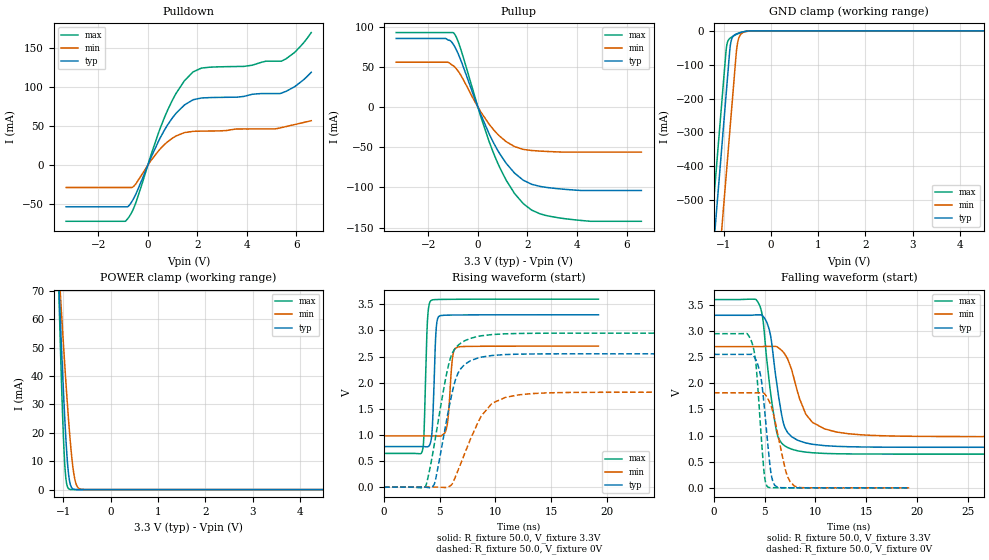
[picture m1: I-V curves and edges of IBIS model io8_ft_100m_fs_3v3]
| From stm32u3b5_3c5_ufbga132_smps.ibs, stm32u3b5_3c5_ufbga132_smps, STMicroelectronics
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[Model]   io8_ft_100m_fs_3v3
Model_type I/O
Polarity   Non-Inverting
Enable   Active-Low
| CAP_THRESHOLD on pad IOFT is "UDTCAPC" :
| Rising=30.0% of vddiom   Falling=70.0% of vddiom
| C_comp min and max val. don't necessarily correlate with the min and max pvt
| but are the smallest and greatest pad capacitance found.
| var   typ   min   max
C_comp   3.79549pF  3.74406pF  3.79817pF
|C_comp_pullup   2.32785pF  2.17309pF  2.40205pF
|C_comp_pulldown   1.46764pF  1.57097pF  1.39612pF
Vinl = 1.35V
Vinh = 1.8V
Vmeas = 1.65V   | Reference voltage for timing measurements
Cref  = 50.0pF   | Timing specification test load capacitance value
Rref  = 1.0MOhm   | Timing specification test load resistance value
Vref  = 1.815V   | Timing specification test load voltage
[Model Spec]
| TIME_THRESHOLD on pin ZIV11 is "CMOS" :
| Rising=50.0% of vdd   Falling=50.0% of vdd
Vinl 1.27950V 1.06950V 1.36550V
Vinh 1.78950V 1.51350V 1.89450V
| variable   typ   min   max
[Temperature Range] 25.0 130.0 -40.0
| variable   typ   min   max
[Voltage Range] 3.3V 2.7V 3.6V
| variable   typ   min   max
[POWER Clamp Reference] 3.3V 2.7V 3.6V
| variable   typ   min   max
[GND Clamp Reference] 0V 0V 0V
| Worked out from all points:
|   slope of the pulldown table from 0 to 0.495 V, typ, clamps not added: 14.3 ohm
|   slope of the pullup table from 0 to 0.495 V, typ, clamps not added: 13.8 ohm
|   GND clamp passes 1 mA (typ) near -0.50 V on its own axis
|   POWER clamp passes 1 mA (typ) near -0.83 V on its own axis
|   rising waveform, R_fixture 50.0, V_fixture 3.3V: 20-80 % time 252ps typ, 335ps min, 240ps max; typ from 0.776 V to 3.3 V
|   falling waveform, R_fixture 50.0, V_fixture 3.3V: 20-80 % time 1.13ns typ, 1.93ns min, 1.08ns max; typ from 3.3 V to 0.776 V
|   rising waveform, R_fixture 50.0, V_fixture 0V: 20-80 % time 1.44ns typ, 2.37ns min, 1.49ns max; typ from 0 V to 2.55 V
|   falling waveform, R_fixture 50.0, V_fixture 0V: 20-80 % time 791ps typ, 1.22ns min, 669ps max; typ from 2.55 V to 0 V
[POWER Clamp]
-3.3V     1.126A     769.5mA    1.647A
-1.1V     75.38mA    79.63mA    73.18mA
-1.09V    71.2mA     76.8mA     67.14mA
-1.08V    67.05mA    73.98mA    61.2mA
-1.06V    58.89mA    68.38mA    49.67mA
-1.01V    39.47mA    54.71mA    24.03mA
-970mV    25.49mA    44.18mA    9.257mA
-930mV    13.81mA    34.16mA    2.168mA
-870mV    3.251mA    20.56mA    140.6uA
-760mV    67.19uA    3.98mA     739.8nA
-630mV    518.7nA    149.1uA    1.803nA
6.6V      0A         0A         0A
[GND Clamp]
-3.3V     -4.191A    -4.432A    -4.059A
-1.25V    -706mA     -946.8mA   -573.6mA
-950mV    -196mA     -436.8mA   -63.63mA
-940mV    -179mA     -419.8mA   -50.26mA
-910mV    -128mA     -368.8mA   -31.05mA
-850mV    -37.37mA   -266.8mA   -20.53mA
-810mV    -18.79mA   -198.8mA   -16.88mA
-720mV    -8.735mA   -51.28mA   -10.12mA
-680mV    -6.635mA   -22.61mA   -7.598mA
-630mV    -4.51mA    -9.474mA   -4.925mA
-400mV    -114.4uA   -369.6uA   -46.93uA
6.6V      2.22nA     299.7nA    1.002nA
| variable   typ   min   max
[Pullup Reference] 3.3V 2.7V 3.6V
| variable   typ   min   max
[Pulldown Reference] 0V 0V 0V
[Pullup]
-3.3V     85.47mA    55.95mA    92.79mA
-1.31V    85.47mA    55.95mA    92.79mA
-950mV    75.9mA     50.36mA    91.24mA
-710mV    59.85mA    40.58mA    73.66mA
120mV     -9.578mA   -6.208mA   -12.33mA
650mV     -45.52mA   -28.81mA   -58.82mA
1.14V     -69.93mA   -42.96mA   -90.97mA
1.83V     -90.96mA   -52.61mA   -120.1mA
2.51V     -98.71mA   -54.73mA   -132.8mA
3.3V      -101.8mA   -55.87mA   -138mA
4.55V     -103.8mA   -56.04mA   -142.1mA
6.6V      -103.8mA   -56.04mA   -142.1mA
[Pulldown]
-3.3V     -53.27mA   -28.52mA   -71.84mA
-840mV    -53.27mA   -28.52mA   -69.65mA
-500mV    -38.18mA   -24.47mA   -49.51mA
460mV     32.61mA    19.53mA    43.99mA
800mV     51.7mA     30.09mA    70.55mA
1.14V     66.56mA    37.47mA    92mA
1.48V     77.24mA    41.82mA    108.3mA
1.83V     83.91mA    43.43mA    119.6mA
2.17V     86.16mA    43.73mA    124.5mA
5.39V     92.36mA    48.12mA    133.3mA
5.93V     100.6mA    52.1mA     144.5mA
6.6V      119.1mA    57.05mA    170mA
[Ramp]
dV/dt_r 1.53142V/1.43454ns 1.09016V/2.27321ns 1.76896V/1.48949ns
dV/dt_f 1.51461V/1.12411ns 1.03189V/1.8419ns 1.77292V/1.08048ns
R_load = 50.0
| Removed startup time: 0s 0s 0s  .
| Removed end time: 19.25ns.
[Rising Waveform]
R_fixture   = 50.0
V_fixture   = 3.3V
V_fixture_min = 2.7V
V_fixture_max = 3.6V
0s        775.7mV    980.2mV    645.1mV
3.45ns    775.7mV    980.2mV    694.1mV
3.6ns     775.5mV    980.2mV    1.054V
3.9ns     772.2mV    980.2mV    3.175V
4.25ns    925mV      980.2mV    3.577V
4.65ns    2.913V     979.9mV    3.591V
4.95ns    3.273V     977mV      3.594V
5.65ns    3.293V     1.16V      3.596V
6.4ns     3.296V     2.659V     3.597V
19.25ns   3.3V       2.7V       3.6V
| Removed startup time: 0s 0s 0s  .
| Removed end time: 59.25ns.
[Falling Waveform]
R_fixture   = 50.0
V_fixture   = 3.3V
V_fixture_min = 2.7V
V_fixture_max = 3.6V
0s        3.3V       2.7V       3.6V
4.3ns     3.308V     2.7V       3.561V
4.8ns     3.287V     2.701V     3.245V
5.45ns    3.018V     2.706V     2.013V
6.25ns    1.907V     2.691V     1.013V
7ns       1.145V     2.55V      800.4mV
8.2ns     914.9mV    1.857V     710.2mV
9.7ns     833.5mV    1.253V     670.8mV
13.3ns    786.4mV    1.034V     649.1mV
59.25ns   775.7mV    980.2mV    645.1mV
| Removed startup time: 0s 0s 0s  .
| Removed end time: 59.25ns.
[Rising Waveform]
R_fixture   = 50.0
V_fixture   = 0V
V_fixture_min = 0V
V_fixture_max = 0V
0s        11.22nV    82.64nV    22.9nV
3.65ns    -180uV     3.707uV    -4.164mV
4.45ns    31.45mV    61.28uV    732.8mV
5.45ns    1.081V     -8.278mV   1.983V
6.05ns    1.74V      41.81mV    2.521V
6.9ns     2.27V      454.1mV    2.758V
8.45ns    2.475V     1.245V     2.887V
9.7ns     2.52V      1.605V     2.921V
13.3ns    2.55V      1.791V     2.945V
59.25ns   2.552V     1.817V     2.948V
| Removed startup time: 0s 0s 0s  .
| Removed end time: 19.25ns.
[Falling Waveform]
R_fixture   = 50.0
V_fixture   = 0V
V_fixture_min = 0V
V_fixture_max = 0V
0s        2.552V     1.817V     2.948V
3.7ns     2.555V     1.817V     2.797V
4.15ns    2.436V     1.817V     2.33V
4.6ns     2.135V     1.817V     1.119V
4.95ns    1.557V     1.805V     264.4mV
5.3ns     832.7mV    1.707V     15.77mV
5.95ns    60.12mV    1.333V     2.628mV
7.1ns     2.376mV    301.9mV    1.359mV
7.9ns     1.559mV    38.81mV    1.042mV
19.25ns   29.52uV    82.76uV    26.06uV
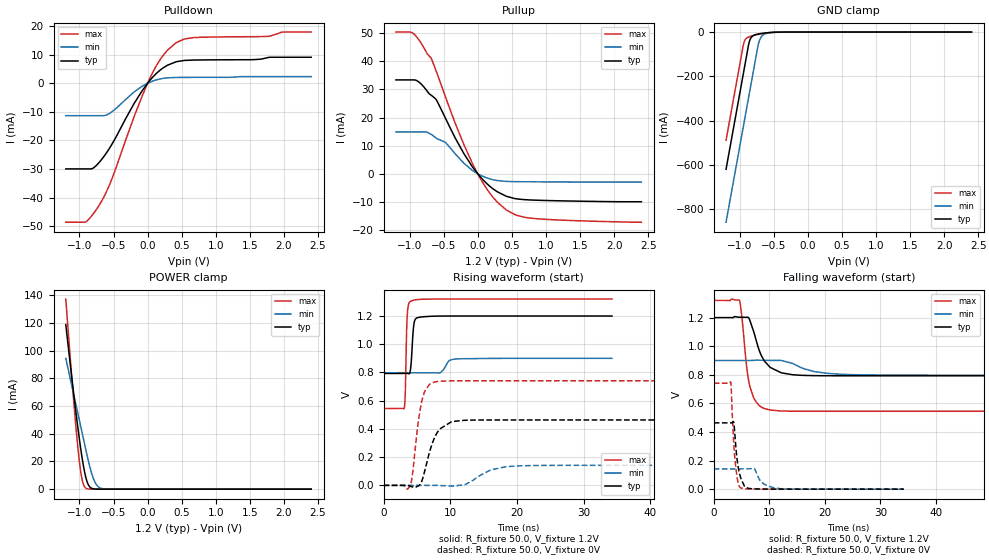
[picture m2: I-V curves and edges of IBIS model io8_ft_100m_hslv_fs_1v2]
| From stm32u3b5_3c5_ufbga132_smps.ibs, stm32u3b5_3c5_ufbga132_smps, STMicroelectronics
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[Model]   io8_ft_100m_hslv_fs_1v2
Model_type I/O
Polarity   Non-Inverting
Enable   Active-Low
| CAP_THRESHOLD on pad IOFT is "UDTCAPC" :
| Rising=30.0% of vddiom   Falling=70.0% of vddiom
| C_comp min and max val. don't necessarily correlate with the min and max pvt
| but are the smallest and greatest pad capacitance found.
| var   typ   min   max
C_comp   2.92730pF  2.86805pF  2.98035pF
|C_comp_pullup   1.66514pF  1.49591pF  1.80350pF
|C_comp_pulldown   1.26216pF  1.37214pF  1.17685pF
Vinl = 450.0mV
Vinh = 660.0mV
Vmeas = 600.0mV   | Reference voltage for timing measurements
Cref  = 50.0pF   | Timing specification test load capacitance value
Rref  = 1.0MOhm   | Timing specification test load resistance value
Vref  = 660.0mV   | Timing specification test load voltage
[Model Spec]
| TIME_THRESHOLD on pin ZIV11 is "CMOS" :
| Rising=50.0% of vdd   Falling=50.0% of vdd
Vinl 439.50000mV 331.50001mV 485.50000mV
Vinh 752.50000mV 552.50001mV 837.50000mV
| variable   typ   min   max
[Temperature Range] 25.0 130.0 -40.0
| variable   typ   min   max
[Voltage Range] 1.2V 900.0mV 1.32V
| variable   typ   min   max
[POWER Clamp Reference] 1.2V 900.0mV 1.32V
| variable   typ   min   max
[GND Clamp Reference] 0V 0V 0V
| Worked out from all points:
|   slope of the pulldown table from 0 to 0.18 V, typ, clamps not added: 40 ohm
|   slope of the pullup table from 0 to 0.18 V, typ, clamps not added: 40 ohm
|   GND clamp passes 1 mA (typ) near -0.50 V on its own axis
|   POWER clamp passes 1 mA (typ) near -0.83 V on its own axis
|   rising waveform, R_fixture 50.0, V_fixture 1.2V: 20-80 % time 341ps typ, 816ps min, 225ps max; typ from 0.793 V to 1.2 V
|   falling waveform, R_fixture 50.0, V_fixture 1.2V: 20-80 % time 2.58ns typ, 4.75ns min, 1.49ns max; typ from 1.2 V to 0.793 V
|   rising waveform, R_fixture 50.0, V_fixture 0V: 20-80 % time 1.89ns typ, 3.34ns min, 1.21ns max; typ from 0 V to 0.464 V
|   falling waveform, R_fixture 50.0, V_fixture 0V: 20-80 % time 927ps typ, 1.77ns min, 723ps max; typ from 0.464 V to 0 V
[POWER Clamp]
-1.2V     118.8mA    94.44mA    137.2mA
-1.09V    71.2mA     69.75mA    67.14mA
-1.02V    43.22mA    54.03mA    28.67mA
-990mV    32.26mA    47.3mA     15.78mA
-970mV    25.49mA    42.81mA    9.257mA
-940mV    16.45mA    36.08mA    3.257mA
-910mV    9.238mA    29.34mA    904.6uA
-860mV    2.387mA    18.53mA    87.46uA
-790mV    204.6uA    7.049mA    3.101uA
-730mV    21.91uA    2.041mA    176.4nA
-660mV    1.594uA    337.6uA    6.282nA
2.4V      0A         0A         0A
[GND Clamp]
-1.2V     -619mA     -857.5mA   -488.2mA
-950mV    -194mA     -432.5mA   -63.18mA
-930mV    -160mA     -398.5mA   -40.87mA
-870mV    -57.95mA   -296.5mA   -22.39mA
-840mV    -28.97mA   -245.5mA   -19.16mA
-800mV    -15.67mA   -177.5mA   -15.71mA
-730mV    -8.807mA   -59.89mA   -10.55mA
-700mV    -7.204mA   -30.66mA   -8.61mA
-660mV    -5.427mA   -13.83mA   -6.309mA
-580mV    -2.713mA   -4.125mA   -2.796mA
-380mV    -62.64uA   -240.2uA   -21.17uA
2.4V      834.9pA    121.9nA    346.5pA
| variable   typ   min   max
[Pullup Reference] 1.2V 900.0mV 1.32V
| variable   typ   min   max
[Pulldown Reference] 0V 0V 0V
[Pullup]
-1.2V     33.4mA     14.9mA     50.41mA
-950mV    33.4mA     14.9mA     49.99mA
-850mV    32.39mA    14.9mA     47.21mA
-680mV    27.9mA     13.97mA    40.97mA
-610mV    26.44mA    12.68mA    36.56mA
-470mV    19.6mA     11.05mA    27.15mA
-330mV    12.72mA    7.084mA    17.97mA
-80mV     2.558mA    1.232mA    3.812mA
170mV     -4.293mA   -1.755mA   -6.654mA
420mV     -8mA       -2.709mA   -12.87mA
790mV     -9.331mA   -2.845mA   -15.82mA
2.4V      -9.943mA   -2.948mA   -17.22mA
[Pulldown]
-1.2V     -29.93mA   -11.33mA   -48.55mA
-910mV    -29.93mA   -11.33mA   -48.48mA
-810mV    -29.8mA    -11.33mA   -46.03mA
-710mV    -27.65mA   -11.33mA   -42.6mA
-530mV    -21.58mA   -10.08mA   -33.79mA
-200mV    -7.157mA   -3.075mA   -11.82mA
40mV      1.18mA     424.7uA    2.081mA
230mV     5.395mA    1.701mA    9.799mA
420mV     7.512mA    2.016mA    14.19mA
670mV     8.097mA    2.046mA    15.93mA
1.78V     9.043mA    2.312mA    16.4mA
2.4V      9.076mA    2.312mA    17.87mA
[Ramp]
dV/dt_r 278.14197mV/1.88608ns 85.19613mV/3.2097ns 444.65521mV/1.21462ns
dV/dt_f 244.20919mV/2.48597ns 61.55849mV/4.61332ns 465.10779mV/1.45148ns
R_load = 50.0
| Removed startup time: 0s 0s 0s  .
| Removed end time: 34.25ns.
[Rising Waveform]
R_fixture   = 50.0
V_fixture   = 1.2V
V_fixture_min = 900.0mV
V_fixture_max = 1.32V
0s        793mV      797.4mV    544.8mV
3.1ns     793.2mV    797.4mV    549mV
3.25ns    793.3mV    797.4mV    657.5mV
3.45ns    793.6mV    797.4mV    1.102V
3.55ns    793.6mV    797.4mV    1.213V
4.05ns    830.1mV    797.4mV    1.305V
4.5ns     1.129V     797.4mV    1.312V
4.95ns    1.186V     797.4mV    1.316V
11.2ns    1.2V       896.4mV    1.32V
34.25ns   1.2V       900mV      1.32V
| Removed startup time: 0s 0s 0s  .
| Removed end time: 99.25ns.
[Falling Waveform]
R_fixture   = 50.0
V_fixture   = 1.2V
V_fixture_min = 900.0mV
V_fixture_max = 1.32V
0s        1.2V       900mV      1.32V
4.6ns     1.203V     900mV      1.322V
5.05ns    1.202V     900mV      1.207V
5.95ns    1.202V     900mV      845.7mV
6.5ns     1.18V      900mV      717.5mV
8.55ns    935.2mV    901.7mV    574.4mV
10.15ns   851.8mV    900.7mV    553.5mV
14.2ns    800.4mV    879.3mV    545.3mV
24.3ns    793mV      801.6mV    544.8mV
99.25ns   793mV      797.4mV    544.8mV
| Removed startup time: 0s 0s 0s  .
| Removed end time: 99.2ns.
[Rising Waveform]
R_fixture   = 50.0
V_fixture   = 0V
V_fixture_min = 0V
V_fixture_max = 0V
0s        4.62nV     136.5nV    3.245nV
3.95ns    -5.089mV   -3.435uV   -5.224mV
4.3ns     -10.2mV    -2.217uV   70.45mV
5.3ns     -1.186mV   -1.818uV   484.3mV
5.85ns    48.05mV    -1.951uV   621.1mV
6.8ns     221.9mV    -21.26uV   711.9mV
8.1ns     379.3mV    39.55uV    735.9mV
10.4ns    452.8mV    -4.74mV    740.5mV
20.25ns   463.5mV    138.4mV    741mV
99.2ns    463.6mV    142mV      741.1mV
| Removed startup time: 0s 0s 0s  .
| Removed end time: 34.2ns.
[Falling Waveform]
R_fixture   = 50.0
V_fixture   = 0V
V_fixture_min = 0V
V_fixture_max = 0V
0s        463.6mV    142mV      741.1mV
3.05ns    463.9mV    142mV      751.1mV
3.55ns    472.3mV    142mV      351.9mV
3.8ns     381.2mV    142mV      214.8mV
4.25ns    191.3mV    142mV      71.92mV
4.85ns    79.01mV    142mV      9.14mV
6.3ns     4.92mV     142.1mV    1.18mV
9ns       732.7uV    36.73mV    160.6uV
11.2ns    242.3uV    7.201mV    41uV
34.2ns    158.3nV    2.704uV    6.272nV
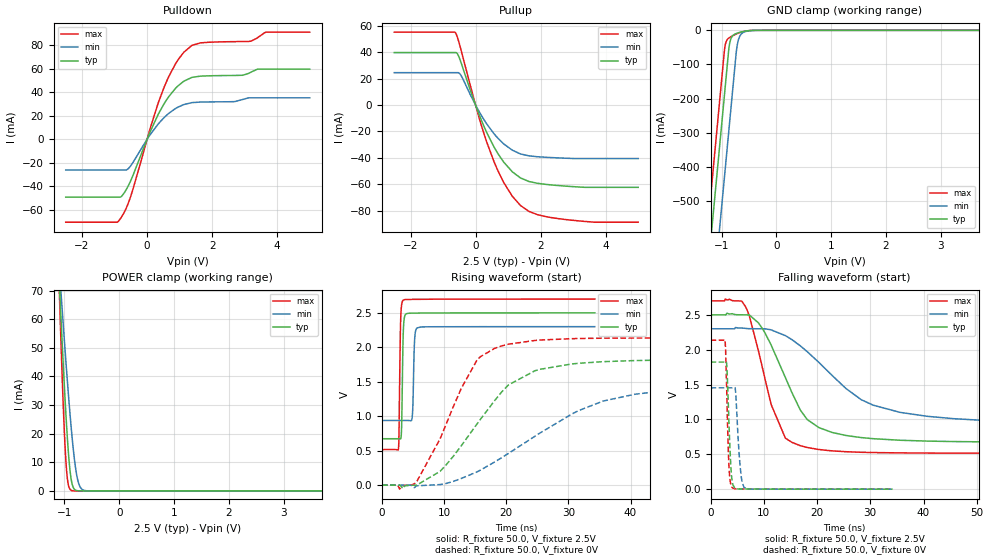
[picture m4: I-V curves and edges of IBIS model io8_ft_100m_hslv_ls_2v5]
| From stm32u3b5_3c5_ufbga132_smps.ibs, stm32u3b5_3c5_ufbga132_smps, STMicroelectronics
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[Model]   io8_ft_100m_hslv_ls_2v5
Model_type I/O
Polarity   Non-Inverting
Enable   Active-Low
| CAP_THRESHOLD on pad IOFT is "UDTCAPC" :
| Rising=30.0% of vddiom   Falling=70.0% of vddiom
| C_comp min and max val. don't necessarily correlate with the min and max pvt
| but are the smallest and greatest pad capacitance found.
| var   typ   min   max
C_comp   3.68189pF  3.67093pF  3.72543pF
|C_comp_pullup   2.08676pF  2.19312pF  2.32495pF
|C_comp_pulldown   1.59513pF  1.47781pF  1.40048pF
Vinl = 1.15V
Vinh = 1.35V
Vmeas = 1.25V   | Reference voltage for timing measurements
Cref  = 50.0pF   | Timing specification test load capacitance value
Rref  = 1.0MOhm   | Timing specification test load resistance value
Vref  = 1.375V   | Timing specification test load voltage
[Model Spec]
| TIME_THRESHOLD on pin ZIV11 is "CMOS" :
| Rising=50.0% of vdd   Falling=50.0% of vdd
Vinl 981.50000mV 911.50000mV 1.04650V
Vinh 1.42350V 1.31650V 1.50350V
| variable   typ   min   max
[Temperature Range] 25.0 130.0 -40.0
| variable   typ   min   max
[Voltage Range] 2.5V 2.3V 2.7V
| variable   typ   min   max
[POWER Clamp Reference] 2.5V 2.3V 2.7V
| variable   typ   min   max
[GND Clamp Reference] 0V 0V 0V
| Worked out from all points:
|   slope of the pulldown table from 0 to 0.375 V, typ, clamps not added: 16.4 ohm
|   slope of the pullup table from 0 to 0.375 V, typ, clamps not added: 16.7 ohm
|   GND clamp passes 1 mA (typ) near -0.50 V on its own axis
|   POWER clamp passes 1 mA (typ) near -0.83 V on its own axis
|   rising waveform, R_fixture 50.0, V_fixture 2.5V: 20-80 % time 198ps typ, 218ps min, 200ps max; typ from 0.673 V to 2.5 V
|   falling waveform, R_fixture 50.0, V_fixture 2.5V: 20-80 % time 6.84ns typ, 13.1ns min, 4.79ns max; typ from 2.5 V to 0.673 V
|   rising waveform, R_fixture 50.0, V_fixture 0V: 20-80 % time 9.46ns typ, 16.7ns min, 6.77ns max; typ from 0 V to 1.82 V
|   falling waveform, R_fixture 50.0, V_fixture 0V: 20-80 % time 563ps typ, 721ps min, 469ps max; typ from 1.82 V to 0 V
[POWER Clamp]
-2.5V     736.6mA    513.9mA    1.064A
-1.1V     75.38mA    79.63mA    73.18mA
-1.09V    71.2mA     76.8mA     67.14mA
-1.08V    67.05mA    73.98mA    61.2mA
-1.06V    58.89mA    68.38mA    49.67mA
-1.02V    43.22mA    57.4mA     28.67mA
-980mV    28.81mA    46.77mA    12.28mA
-940mV    16.45mA    36.61mA    3.257mA
-880mV    4.35mA     22.67mA    225.4uA
-770mV    97.5uA     4.87mA     1.193uA
-630mV    518.5nA    149.1uA    1.636nA
5V        0A         0A         0A
[GND Clamp]
-2.5V     -2.831A    -3.071A    -2.699A
-1.46V    -1.063A    -1.303A    -931.1mA
-1.21V    -637.8mA   -878.3mA   -506.1mA
-950mV    -195.8mA   -436.3mA   -64.07mA
-940mV    -178.8mA   -419.3mA   -50.67mA
-910mV    -127.8mA   -368.3mA   -31.36mA
-850mV    -37.25mA   -266.3mA   -20.72mA
-750mV    -10.68mA   -96.33mA   -12.3mA
-710mV    -8.126mA   -41.01mA   -9.515mA
-670mV    -6.142mA   -18.5mA    -7.051mA
-470mV    -612.4uA   -1.154mA   -431uA
5V        1.687nA    211.8nA    737.8pA
| variable   typ   min   max
[Pullup Reference] 2.5V 2.3V 2.7V
| variable   typ   min   max
[Pulldown Reference] 0V 0V 0V
[Pullup]
-2.5V     39.82mA    24.56mA    55.36mA
-620mV    39.82mA    24.56mA    54.9mA
-550mV    38.54mA    24.56mA    50.78mA
-450mV    32.5mA     22.56mA    42.09mA
130mV     -8.475mA   -5.821mA   -11.39mA
560mV     -31.46mA   -21.52mA   -42.47mA
870mV     -43.43mA   -29.56mA   -58.95mA
1.38V     -55.27mA   -37.08mA   -76.15mA
1.9V      -59.33mA   -39.2mA    -83.14mA
2.5V      -60.98mA   -40.04mA   -86.01mA
3.65V     -62.43mA   -40.58mA   -88.86mA
5V        -62.43mA   -40.58mA   -88.86mA
[Pulldown]
-2.5V     -49.09mA   -26.02mA   -70.37mA
-920mV    -49.09mA   -26.02mA   -70.37mA
-830mV    -49.09mA   -26.02mA   -67.8mA
-510mV    -35.57mA   -22.69mA   -49.05mA
90mV      6.138mA    3.798mA    8.848mA
520mV     30.1mA     18.41mA    43.96mA
940mV     45.18mA    27.25mA    67.1mA
1.38V     52.7mA     31.24mA    79.88mA
2.68V     54.32mA    32.09mA    83.06mA
3.2V      57.2mA     35.33mA    83.52mA
3.67V     59.71mA    35.33mA    91.16mA
5V        59.71mA    35.33mA    91.17mA
[Ramp]
dV/dt_r 1.09344V/9.4136ns 871.74695mV/16.4349ns 1.28161V/6.33006ns
dV/dt_f 1.09609V/6.73846ns 816.97073mV/13.03491ns 1.31053V/4.21821ns
R_load = 50.0
| Removed startup time: 0s 0s 0s  .
| Removed end time: 34.25ns.
[Rising Waveform]
R_fixture   = 50.0
V_fixture   = 2.5V
V_fixture_min = 2.3V
V_fixture_max = 2.7V
0s        673.2mV    938.4mV    515.8mV
2.65ns    673.1mV    938.4mV    529.8mV
3ns       671.3mV    938.4mV    2.405V
3.15ns    837.9mV    938.4mV    2.617V
3.4ns     2.17V      938.4mV    2.683V
3.7ns     2.465V     938.4mV    2.692V
4.85ns    2.496V     981.1mV    2.695V
5.25ns    2.496V     2.119V     2.696V
5.65ns    2.497V     2.282V     2.696V
34.25ns   2.5V       2.3V       2.7V
| Removed startup time: 0s 0s 0s  .
| Removed end time: 249.25ns.
[Falling Waveform]
R_fixture   = 50.0
V_fixture   = 2.5V
V_fixture_min = 2.3V
V_fixture_max = 2.7V
0s        2.5V       2.3V       2.7V
5.95ns    2.5V       2.31V      2.688V
9ns       2.384V     2.3V       1.981V
11.4ns    2.063V     2.284V     1.21V
14.05ns   1.601V     2.202V     731.9mV
16.85ns   1.136V     2.056V     623.9mV
20.35ns   882.9mV    1.817V     568.3mV
30.55ns   723.8mV    1.204V     525.1mV
50.9ns    678.8mV    987.9mV    516.3mV
249.3ns   673.2mV    938.4mV    515.8mV
| Removed startup time: 0s 0s 0s  .
| Removed end time: 249.25ns.
[Rising Waveform]
R_fixture   = 50.0
V_fixture   = 0V
V_fixture_min = 0V
V_fixture_max = 0V
0s        5.221nV    85.5nV     4.317nV
5.6ns     438.2uV    -9.215mV   52.91mV
9.35ns    200.9mV    8.021mV    673.1mV
12.75ns   570.6mV    96.74mV    1.402V
15.85ns   956.2mV    218.8mV    1.864V
20.35ns   1.454V     460.4mV    2.045V
24.6ns    1.659V     708.5mV    2.099V
35.6ns    1.792V     1.22V      2.132V
55.95ns   1.821V     1.421V     2.136V
249.3ns   1.822V     1.453V     2.136V
| Removed startup time: 0s 0s 0s  .
| Removed end time: 34.2ns.
[Falling Waveform]
R_fixture   = 50.0
V_fixture   = 0V
V_fixture_min = 0V
V_fixture_max = 0V
0s        1.822V     1.453V     2.136V
2.7ns     1.823V     1.453V     2.143V
3.05ns    1.771V     1.453V     1.38V
3.45ns    962.3mV    1.453V     339.9mV
3.8ns     344.1mV    1.453V     69.71mV
4.15ns    77.68mV    1.453V     16.84mV
4.65ns    11.43mV    1.435V     4.722mV
5.5ns     2.572mV    377.2mV    3.044mV
6.3ns     2.093mV    24.15mV    3.28mV
34.2ns    79.84uV    183.8uV    33.72uV
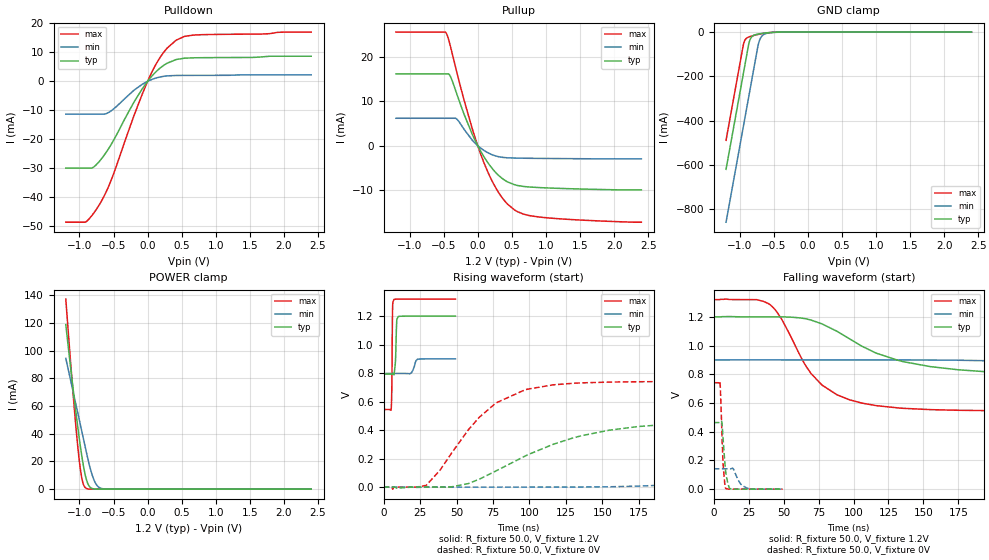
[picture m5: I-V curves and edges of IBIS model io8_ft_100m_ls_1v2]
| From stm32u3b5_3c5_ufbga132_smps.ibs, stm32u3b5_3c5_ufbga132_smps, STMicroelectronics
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[Model]   io8_ft_100m_ls_1v2
Model_type I/O
Polarity   Non-Inverting
Enable   Active-Low
| CAP_THRESHOLD on pad IOFT is "UDTCAPC" :
| Rising=30.0% of vddiom   Falling=70.0% of vddiom
| C_comp min and max val. don't necessarily correlate with the min and max pvt
| but are the smallest and greatest pad capacitance found.
| var   typ   min   max
C_comp   2.92097pF  2.86112pF  2.97371pF
|C_comp_pullup   1.65779pF  1.48814pF  1.79576pF
|C_comp_pulldown   1.26319pF  1.37298pF  1.17795pF
Vinl = 450.0mV
Vinh = 660.0mV
Vmeas = 600.0mV   | Reference voltage for timing measurements
Cref  = 50.0pF   | Timing specification test load capacitance value
Rref  = 1.0MOhm   | Timing specification test load resistance value
Vref  = 660.0mV   | Timing specification test load voltage
[Model Spec]
| TIME_THRESHOLD on pin ZIV11 is "CMOS" :
| Rising=50.0% of vdd   Falling=50.0% of vdd
Vinl 439.50000mV 331.50001mV 485.50000mV
Vinh 752.50000mV 552.50001mV 837.50000mV
| variable   typ   min   max
[Temperature Range] 25.0 130.0 -40.0
| variable   typ   min   max
[Voltage Range] 1.2V 900.0mV 1.32V
| variable   typ   min   max
[POWER Clamp Reference] 1.2V 900.0mV 1.32V
| variable   typ   min   max
[GND Clamp Reference] 0V 0V 0V
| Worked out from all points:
|   slope of the pulldown table from 0 to 0.18 V, typ, clamps not added: 40 ohm
|   slope of the pullup table from 0 to 0.18 V, typ, clamps not added: 40 ohm
|   GND clamp passes 1 mA (typ) near -0.50 V on its own axis
|   POWER clamp passes 1 mA (typ) near -0.83 V on its own axis
|   rising waveform, R_fixture 50.0, V_fixture 1.2V: 20-80 % time 717ps typ, 1.99ns min, 395ps max; typ from 0.793 V to 1.2 V
|   falling waveform, R_fixture 50.0, V_fixture 1.2V: 20-80 % time 59ns typ, 145ns min, 31.8ns max; typ from 1.2 V to 0.793 V
|   rising waveform, R_fixture 50.0, V_fixture 0V: 20-80 % time 67.8ns typ, 167ns min, 36.9ns max; typ from 0 V to 0.464 V
|   falling waveform, R_fixture 50.0, V_fixture 0V: 20-80 % time 2.42ns typ, 4.78ns min, 1.77ns max; typ from 0.464 V to 0 V
[POWER Clamp]
-1.2V     118.8mA    94.44mA    137.2mA
-1.09V    71.2mA     69.75mA    67.14mA
-1.02V    43.22mA    54.03mA    28.67mA
-990mV    32.26mA    47.3mA     15.78mA
-970mV    25.49mA    42.81mA    9.257mA
-940mV    16.45mA    36.08mA    3.257mA
-910mV    9.238mA    29.34mA    904.6uA
-860mV    2.387mA    18.53mA    87.46uA
-790mV    204.6uA    7.049mA    3.101uA
-730mV    21.91uA    2.041mA    176.4nA
-660mV    1.594uA    337.6uA    6.285nA
2.4V      0A         0A         0A
[GND Clamp]
-1.2V     -619mA     -857.5mA   -488.2mA
-950mV    -194mA     -432.5mA   -63.18mA
-930mV    -160mA     -398.5mA   -40.87mA
-870mV    -57.95mA   -296.5mA   -22.39mA
-840mV    -28.97mA   -245.5mA   -19.16mA
-800mV    -15.67mA   -177.5mA   -15.71mA
-730mV    -8.807mA   -59.89mA   -10.55mA
-700mV    -7.204mA   -30.66mA   -8.61mA
-660mV    -5.427mA   -13.83mA   -6.309mA
-580mV    -2.713mA   -4.125mA   -2.796mA
-380mV    -62.64uA   -240.2uA   -21.17uA
2.4V      836.4pA    121.5nA    348.6pA
| variable   typ   min   max
[Pullup Reference] 1.2V 900.0mV 1.32V
| variable   typ   min   max
[Pulldown Reference] 0V 0V 0V
[Pullup]
-1.2V     16.16mA    6.167mA    25.56mA
-460mV    16.16mA    6.167mA    25.29mA
-400mV    15.55mA    6.167mA    22.33mA
-310mV    11.77mA    6.024mA    16.72mA
-80mV     2.558mA    1.232mA    3.812mA
80mV      -2.205mA   -948.4uA   -3.386mA
190mV     -4.701mA   -1.897mA   -7.304mA
310mV     -6.737mA   -2.489mA   -10.64mA
540mV     -8.791mA   -2.786mA   -14.47mA
740mV     -9.274mA   -2.836mA   -15.67mA
1.04V     -9.521mA   -2.882mA   -16.26mA
2.4V      -9.943mA   -2.948mA   -17.22mA
[Pulldown]
-1.2V     -29.93mA   -11.33mA   -48.55mA
-910mV    -29.93mA   -11.33mA   -48.48mA
-810mV    -29.8mA    -11.33mA   -46.03mA
-710mV    -27.65mA   -11.33mA   -42.6mA
-620mV    -24.89mA   -11.22mA   -38.69mA
-530mV    -21.58mA   -10.08mA   -33.79mA
-200mV    -7.157mA   -3.075mA   -11.82mA
40mV      1.18mA     424.7uA    2.081mA
230mV     5.395mA    1.701mA    9.799mA
420mV     7.512mA    2.016mA    14.19mA
670mV     8.097mA    2.046mA    15.93mA
2.4V      8.645mA    2.222mA    16.96mA
[Ramp]
dV/dt_r 278.11697mV/66.80941ns 85.09126mV/166.64956ns 444.64736mV/36.82994ns
dV/dt_f 244.21017mV/57.54492ns 61.50161mV/143.94746ns 465.10816mV/31.09214ns
R_load = 50.0
| Removed startup time: 0s 0s 0s  .
| Removed end time: 49.25ns.
[Rising Waveform]
R_fixture   = 50.0
V_fixture   = 1.2V
V_fixture_min = 900.0mV
V_fixture_max = 1.32V
0s        793mV      797.4mV    544.8mV
5.15ns    793mV      797.4mV    546.5mV
5.6ns     793.1mV    797.4mV    699.4mV
6.15ns    792.9mV    797.4mV    1.261V
7.05ns    788.6mV    797.4mV    1.317V
8.05ns    873.3mV    797.4mV    1.319V
9ns       1.168V     797.4mV    1.319V
10.05ns   1.197V     797.4mV    1.319V
23.15ns   1.2V       896.9mV    1.32V
49.25ns   1.2V       899.9mV    1.32V
| Removed startup time: 0s 0s 0s  .
| Removed end time: 949.25ns.
[Falling Waveform]
R_fixture   = 50.0
V_fixture   = 1.2V
V_fixture_min = 900.0mV
V_fixture_max = 1.32V
0s        1.2V       900mV      1.32V
38.75ns   1.2V       900.1mV    1.294V
48.75ns   1.2V       900mV      1.181V
66.3ns    1.185V     900mV      851.8mV
77.5ns    1.151V     900mV      724.4mV
96.85ns   1.049V     900mV      623.4mV
132.6ns   895.2mV    899.9mV    565.1mV
174.3ns   831.9mV    897.9mV    549.5mV
271.2ns   797.7mV    856.4mV    545mV
949.3ns   793mV      797.5mV    544.8mV
| Removed startup time: 0s 0s 0s  .
| Removed end time: 949.25ns.
[Rising Waveform]
R_fixture   = 50.0
V_fixture   = 0V
V_fixture_min = 0V
V_fixture_max = 0V
0s        4.598nV    136nV      3.245nV
29.2ns    -93.86uV   -31.86uV   12.16mV
58.1ns    24.61mV    -22.63uV   402.3mV
77.5ns    115.6mV    -9.731uV   592.7mV
96.85ns   217.1mV    45.63uV    682.3mV
130.1ns   345.5mV    367.5uV    728.8mV
174.3ns   424.7mV    6.773mV    739.4mV
251.9ns   458.3mV    49.39mV    740.9mV
465ns     463.4mV    129.6mV    741mV
949.3ns   463.5mV    141.8mV    741.1mV
| Removed startup time: 0s 0s 0s  .
| Removed end time: 49.25ns.
[Falling Waveform]
R_fixture   = 50.0
V_fixture   = 0V
V_fixture_min = 0V
V_fixture_max = 0V
0s        463.6mV    142mV      741.1mV
4.45ns    463.6mV    142mV      748mV
5.7ns     471.2mV    142mV      425.7mV
6.6ns     361.9mV    142mV      193.2mV
7.8ns     199.7mV    142mV      44.16mV
8.55ns    120.2mV    142mV      5.724mV
10.05ns   41.68mV    142mV      1.474mV
12.05ns   1.785mV    141.8mV    482uV
24.15ns   83.38uV    6.296mV    161.7uV
49.25ns   101.2uV    23.22uV    153.7uV
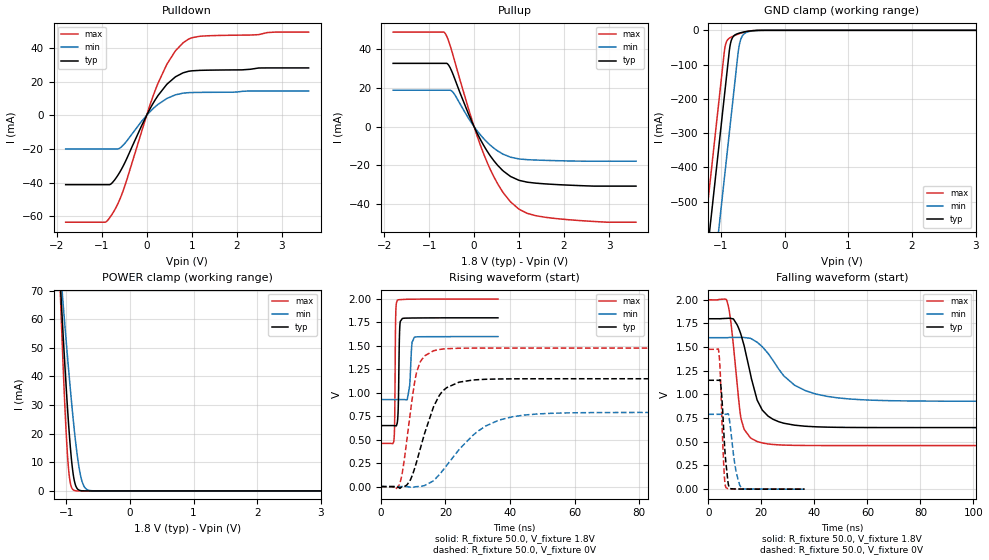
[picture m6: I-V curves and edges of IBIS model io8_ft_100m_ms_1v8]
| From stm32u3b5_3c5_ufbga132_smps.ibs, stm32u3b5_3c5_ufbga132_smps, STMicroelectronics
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[Model]   io8_ft_100m_ms_1v8
Model_type I/O
Polarity   Non-Inverting
Enable   Active-Low
| CAP_THRESHOLD on pad IOFT is "UDTCAPC" :
| Rising=30.0% of vddiom   Falling=70.0% of vddiom
| C_comp min and max val. don't necessarily correlate with the min and max pvt
| but are the smallest and greatest pad capacitance found.
| var   typ   min   max
C_comp   3.41155pF  3.41004pF  3.47580pF
|C_comp_pullup   1.91862pF  1.83561pF  2.09528pF
|C_comp_pulldown   1.49293pF  1.57442pF  1.38051pF
Vinl = 800.0mV
Vinh = 1.0V
Vmeas = 900.0mV   | Reference voltage for timing measurements
Cref  = 50.0pF   | Timing specification test load capacitance value
Rref  = 1.0MOhm   | Timing specification test load resistance value
Vref  = 990.0mV   | Timing specification test load voltage
[Model Spec]
| TIME_THRESHOLD on pin ZIV11 is "CMOS" :
| Rising=50.0% of vdd   Falling=50.0% of vdd
Vinl 694.50000mV 619.50000mV 778.50000mV
Vinh 1.08350V 957.50000mV 1.18750V
| variable   typ   min   max
[Temperature Range] 25.0 130.0 -40.0
| variable   typ   min   max
[Voltage Range] 1.8V 1.6V 2.0V
| variable   typ   min   max
[POWER Clamp Reference] 1.8V 1.6V 2.0V
| variable   typ   min   max
[GND Clamp Reference] 0V 0V 0V
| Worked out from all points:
|   slope of the pulldown table from 0 to 0.27 V, typ, clamps not added: 21.9 ohm
|   slope of the pullup table from 0 to 0.27 V, typ, clamps not added: 22.7 ohm
|   GND clamp passes 1 mA (typ) near -0.50 V on its own axis
|   POWER clamp passes 1 mA (typ) near -0.83 V on its own axis
|   rising waveform, R_fixture 50.0, V_fixture 1.8V: 20-80 % time 317ps typ, 638ps min, 234ps max; typ from 0.65 V to 1.8 V
|   falling waveform, R_fixture 50.0, V_fixture 1.8V: 20-80 % time 6.58ns typ, 13.5ns min, 3.41ns max; typ from 1.8 V to 0.65 V
|   rising waveform, R_fixture 50.0, V_fixture 0V: 20-80 % time 6.55ns typ, 13.1ns min, 3.55ns max; typ from 0 V to 1.15 V
|   falling waveform, R_fixture 50.0, V_fixture 0V: 20-80 % time 1.6ns typ, 2.32ns min, 1.18ns max; typ from 1.15 V to 0 V
[POWER Clamp]
-1.8V     399.1mA    292.1mA    557.7mA
-1.09V    71.2mA     76.8mA     67.14mA
-1.08V    67.05mA    73.98mA    61.2mA
-1.06V    58.89mA    68.38mA    49.67mA
-1.02V    43.22mA    57.4mA     28.67mA
-980mV    28.81mA    46.77mA    12.28mA
-940mV    16.45mA    36.61mA    3.257mA
-880mV    4.35mA     22.67mA    225.4uA
-820mV    610.4uA    11.29mA    13uA
-770mV    97.5uA     4.87mA     1.193uA
-640mV    753.9nA    196uA      2.499nA
3.6V      0A         0A         0A
[GND Clamp]
-1.8V     -1.64A     -1.88A     -1.509A
-1.24V    -688.2mA   -927.9mA   -557mA
-1.05V    -365.2mA   -604.9mA   -234mA
-950mV    -195.2mA   -434.9mA   -64mA
-930mV    -161.2mA   -400.9mA   -41.59mA
-870mV    -59.19mA   -298.9mA   -22.94mA
-850mV    -36.73mA   -264.9mA   -20.65mA
-770mV    -12.21mA   -128.9mA   -13.73mA
-730mV    -9.139mA   -62.1mA    -10.81mA
-690mV    -6.97mA    -26.33mA   -8.198mA
-530mV    -1.564mA   -2.413mA   -1.407mA
3.6V      1.23nA     159nA      530.1pA
| variable   typ   min   max
[Pullup Reference] 1.8V 1.6V 2.0V
| variable   typ   min   max
[Pulldown Reference] 0V 0V 0V
[Pullup]
-1.8V     32.77mA    18.86mA    48.96mA
-640mV    32.77mA    18.86mA    48.22mA
-560mV    31.64mA    18.86mA    43.94mA
-460mV    26.62mA    17.53mA    36.31mA
0V        512.9fA    124pA      3fA
280mV     -12.28mA   -7.824mA   -17.91mA
630mV     -22.57mA   -14.06mA   -33.59mA
810mV     -25.79mA   -15.81mA   -38.95mA
1V        -27.82mA   -16.74mA   -42.77mA
1.37V     -29.26mA   -17.3mA    -46.1mA
1.74V     -29.87mA   -17.57mA   -47.39mA
3.6V      -30.8mA    -17.88mA   -49.48mA
[Pulldown]
-1.8V     -41.16mA   -19.96mA   -63.43mA
-920mV    -41.16mA   -19.96mA   -63.43mA
-780mV    -40.43mA   -19.96mA   -59.18mA
-620mV    -34.74mA   -19.77mA   -51.3mA
-510mV    -29.46mA   -17.38mA   -43.8mA
0V        0A         0A         0A
250mV     11.64mA    6.428mA    18.87mA
460mV     18.67mA    10.12mA    30.76mA
630mV     22.61mA    12.05mA    37.86mA
810mV     25.21mA    13.14mA    43.03mA
1.18V     26.67mA    13.59mA    46.9mA
3.6V      28.11mA    14.46mA    49.37mA
[Ramp]
dV/dt_r 690.02361mV/6.45696ns 474.35472mV/12.98337ns 886.36696mV/3.5462ns
dV/dt_f 689.75467mV/6.37935ns 403.00324mV/13.15662ns 923.6805mV/3.39584ns
R_load = 50.0
| Removed startup time: 0s 0s 0s  .
| Removed end time: 36.25ns.
[Rising Waveform]
R_fixture   = 50.0
V_fixture   = 1.8V
V_fixture_min = 1.6V
V_fixture_max = 2.0V
0s        650.4mV    928.3mV    460.5mV
4ns       650.4mV    928.3mV    486.4mV
4.25ns    650.2mV    928.3mV    692.6mV
4.6ns     647.6mV    928.3mV    1.856V
5.05ns    677.3mV    928.3mV    1.986V
5.85ns    1.711V     928.3mV    1.994V
6.65ns    1.794V     928.4mV    1.995V
8.15ns    1.797V     927.2mV    1.998V
10.35ns   1.798V     1.594V     1.999V
36.25ns   1.8V       1.6V       2V
| Removed startup time: 0s 0s 0s  .
| Removed end time: 199.25ns.
[Falling Waveform]
R_fixture   = 50.0
V_fixture   = 1.8V
V_fixture_min = 1.6V
V_fixture_max = 2.0V
0s        1.8V       1.6V       2V
6.95ns    1.804V     1.6V       1.996V
8.65ns    1.802V     1.603V     1.728V
12.4ns    1.624V     1.603V     735.7mV
13.5ns    1.515V     1.602V     631.9mV
18.4ns    941.1mV    1.552V     503.7mV
20.35ns   835mV      1.505V     488mV
32.55ns   675.8mV    1.097V     462.6mV
48.8ns    653.1mV    964.4mV    460.6mV
199.3ns   650.4mV    928.3mV    460.5mV
| Removed startup time: 0s 0s 0s  .
| Removed end time: 199.2ns.
[Rising Waveform]
R_fixture   = 50.0
V_fixture   = 0V
V_fixture_min = 0V
V_fixture_max = 0V
0s        4.649nV    97.48nV    3.434nV
5.7ns     -15.12mV   1.201uV    22.37mV
6.95ns    -1.197mV   24.09uV    219.1mV
9.15ns    72.29mV    -6.465mV   799.8mV
11.1ns    269.7mV    -987.9uV   1.227V
13.5ns    564.5mV    10.18mV    1.394V
18.05ns   970mV      125.4mV    1.462V
30.05ns   1.14V      590.6mV    1.477V
44.75ns   1.15V      763.9mV    1.477V
199.2ns   1.15V      790.6mV    1.477V
| Removed startup time: 0s 0s 0s  .
| Removed end time: 36.25ns.
[Falling Waveform]
R_fixture   = 50.0
V_fixture   = 0V
V_fixture_min = 0V
V_fixture_max = 0V
0s        1.15V      790.6mV    1.477V
3.9ns     1.15V      790.6mV    1.458V
4.35ns    1.156V     790.6mV    1.308V
4.85ns    1.052V     790.6mV    971.3mV
5.85ns    591.4mV    790.6mV    230.8mV
6.65ns    271.9mV    790.6mV    16.3mV
8.15ns    8.539mV    693.1mV    2.785mV
10.35ns   2.031mV    202mV      850.5uV
12.6ns    1.005mV    8.407mV    482.9uV
36.25ns   31.55uV    154.3uV    4.325uV
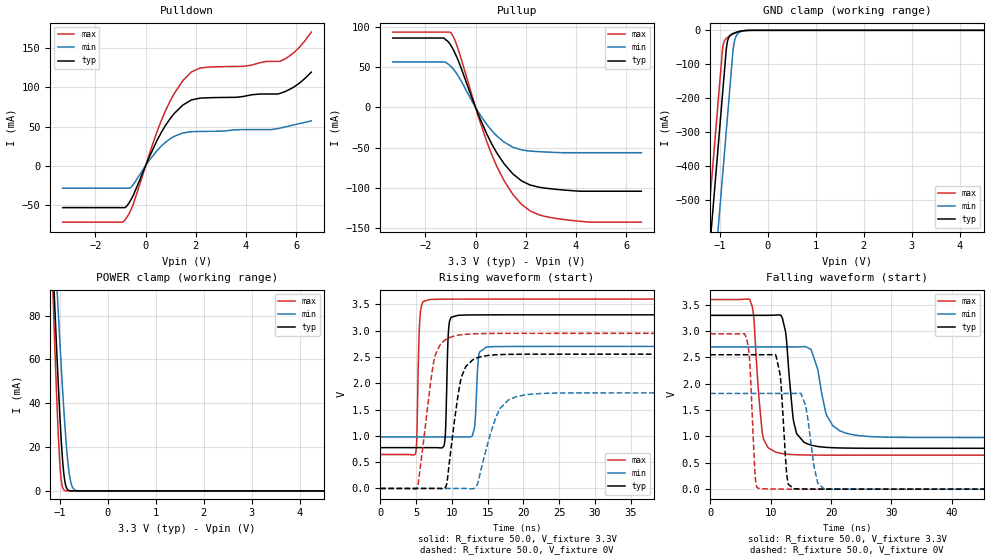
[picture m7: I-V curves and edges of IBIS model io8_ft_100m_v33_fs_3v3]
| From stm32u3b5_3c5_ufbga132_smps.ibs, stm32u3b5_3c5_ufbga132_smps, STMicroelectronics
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[Model]   io8_ft_100m_v33_fs_3v3
Model_type I/O
Polarity   Non-Inverting
Enable   Active-Low
| CAP_THRESHOLD on pad IOFT is "UDTCAPC" :
| Rising=30.0% of vddiom   Falling=70.0% of vddiom
| C_comp min and max val. don't necessarily correlate with the min and max pvt
| but are the smallest and greatest pad capacitance found.
| var   typ   min   max
C_comp   5.13862pF  4.98765pF  5.13964pF
|C_comp_pullup   3.32249pF  3.08556pF  3.41454pF
|C_comp_pulldown   1.81613pF  1.90209pF  1.72510pF
Vinl = 1.35V
Vinh = 1.8V
Vmeas = 1.65V   | Reference voltage for timing measurements
Cref  = 50.0pF   | Timing specification test load capacitance value
Rref  = 1.0MOhm   | Timing specification test load resistance value
Vref  = 1.815V   | Timing specification test load voltage
[Model Spec]
| TIME_THRESHOLD on pin ZIV33M is "CMOS" :
| Rising=50.0% of vddiom   Falling=50.0% of vddiom
Vinl 1.27350V 1.06350V 1.35850V
Vinh 1.78850V 1.51250V 1.89250V
| variable   typ   min   max
[Temperature Range] 25.0 130.0 -40.0
| variable   typ   min   max
[Voltage Range] 3.3V 2.7V 3.6V
| variable   typ   min   max
[POWER Clamp Reference] 3.3V 2.7V 3.6V
| variable   typ   min   max
[GND Clamp Reference] 0V 0V 0V
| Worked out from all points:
|   slope of the pulldown table from 0 to 0.495 V, typ, clamps not added: 14.3 ohm
|   slope of the pullup table from 0 to 0.495 V, typ, clamps not added: 13.8 ohm
|   GND clamp passes 1 mA (typ) near -0.50 V on its own axis
|   POWER clamp passes 1 mA (typ) near -0.85 V on its own axis
|   rising waveform, R_fixture 50.0, V_fixture 3.3V: 20-80 % time 288ps typ, 366ps min, 294ps max; typ from 0.776 V to 3.3 V
|   falling waveform, R_fixture 50.0, V_fixture 3.3V: 20-80 % time 1.16ns typ, 2.11ns min, 1.11ns max; typ from 3.3 V to 0.776 V
|   rising waveform, R_fixture 50.0, V_fixture 0V: 20-80 % time 1.54ns typ, 2.4ns min, 1.63ns max; typ from 0 V to 2.55 V
|   falling waveform, R_fixture 50.0, V_fixture 0V: 20-80 % time 828ps typ, 1.33ns min, 709ps max; typ from 2.55 V to 0 V
[POWER Clamp]
-3.3V     1.376A     1.183A     1.687A
-1.15V    107mA      132mA      94.23mA
-1.14V    101.7mA    127.5mA    87.74mA
-1.11V    86.11mA    114.3mA    68.77mA
-1.05V    56.42mA    88.49mA    34.19mA
-1V       34.12mA    67.92mA    12.34mA
-960mV    19.14mA    52.36mA    3.231mA
-900mV    4.863mA    31.3mA     221.9uA
-840mV    665uA      14.67mA    12.78uA
-790mV    105.7uA    5.908mA    1.173uA
-650mV    562.2nA    165.6uA    2.035nA
6.6V      0A         0A         0A
[GND Clamp]
-3.3V     -4.192A    -4.434A    -4.059A
-1.25V    -707.2mA   -948.8mA   -574.2mA
-950mV    -197.2mA   -438.8mA   -64.18mA
-940mV    -180.2mA   -421.8mA   -51.24mA
-870mV    -61.19mA   -302.8mA   -24.27mA
-850mV    -38.62mA   -268.8mA   -21.84mA
-800mV    -17.58mA   -183.8mA   -16.98mA
-730mV    -9.777mA   -65.72mA   -11.28mA
-710mV    -8.51mA    -43.04mA   -9.847mA
-620mV    -4.247mA   -8.765mA   -4.565mA
-390mV    -85.77uA   -309.6uA   -31.83uA
6.6V      2.503nA    356.6nA    1.779nA
| variable   typ   min   max
[Pullup Reference] 3.3V 2.7V 3.6V
| variable   typ   min   max
[Pulldown Reference] 0V 0V 0V
[Pullup]
-3.3V     86.14mA    56.49mA    93.49mA
-1.28V    86.12mA    56.49mA    93.49mA
-960mV    75.73mA    50.26mA    91.62mA
-710mV    59.63mA    39.99mA    73.75mA
120mV     -9.578mA   -6.208mA   -12.33mA
650mV     -45.52mA   -28.81mA   -58.82mA
1.14V     -69.93mA   -42.96mA   -90.97mA
1.83V     -90.96mA   -52.61mA   -120.1mA
2.51V     -98.71mA   -54.73mA   -132.8mA
3.3V      -101.8mA   -55.87mA   -138mA
4.55V     -103.8mA   -56.04mA   -142.2mA
6.6V      -103.8mA   -56.04mA   -142.2mA
[Pulldown]
-3.3V     -53.27mA   -28.52mA   -71.84mA
-850mV    -53.27mA   -28.52mA   -70.02mA
-500mV    -38.18mA   -24.47mA   -49.51mA
460mV     32.61mA    19.53mA    43.99mA
800mV     51.7mA     30.09mA    70.55mA
1.14V     66.56mA    37.47mA    92mA
1.48V     77.24mA    41.82mA    108.3mA
1.83V     83.91mA    43.43mA    119.6mA
2.17V     86.16mA    43.73mA    124.5mA
5.35V     92.17mA    47.94mA    133mA
5.95V     101.3mA    52.36mA    145.4mA
6.6V      119.3mA    57.17mA    170.3mA
[Ramp]
dV/dt_r 1.53142V/1.54535ns 1.09017V/2.38309ns 1.76896V/1.62888ns
dV/dt_f 1.51461V/1.15882ns 1.03188V/1.8755ns 1.77292V/1.10775ns
R_load = 50.0
| Removed startup time: 0s 0s 0s  .
| Removed end time: 48.4ns.
[Rising Waveform]
R_fixture   = 50.0
V_fixture   = 3.3V
V_fixture_min = 2.7V
V_fixture_max = 3.6V
0s        775.7mV    980.2mV    645.1mV
4.95ns    775.7mV    980.2mV    678.6mV
5.45ns    775.7mV    980.2mV    3.023V
5.95ns    775.7mV    980.2mV    3.551V
8.95ns    838.1mV    980.2mV    3.598V
9.9ns     3.255V     980.2mV    3.599V
12.85ns   3.298V     997.7mV    3.6V
13.75ns   3.299V     2.519V     3.6V
14.85ns   3.3V       2.69V      3.6V
48.4ns    3.3V       2.7V       3.6V
| Removed startup time: 0s 0s 0s  .
| Removed end time: 58.4ns.
[Falling Waveform]
R_fixture   = 50.0
V_fixture   = 3.3V
V_fixture_min = 2.7V
V_fixture_max = 3.6V
0s        3.3V       2.7V       3.6V
6.55ns    3.3V       2.7V       3.601V
8.7ns     3.3V       2.7V       1.013V
10.75ns   3.304V     2.7V       707.2mV
12.45ns   3V         2.7V       667mV
13.8ns    1.287V     2.7V       655.6mV
15.8ns    874.6mV    2.706V     649.1mV
19.25ns   793.1mV    1.408V     646mV
22.65ns   779.8mV    1.057V     645.4mV
58.4ns    775.7mV    980.2mV    645.1mV
| Removed startup time: 0s 0s 0s  .
| Removed end time: 58.4ns.
[Rising Waveform]
R_fixture   = 50.0
V_fixture   = 0V
V_fixture_min = 0V
V_fixture_max = 0V
0s        11.93nV    102.1nV    24.43nV
5.15ns    10.62nV    101.6nV    12.19mV
7.55ns    8.289uV    100.7nV    2.466V
9.15ns    33.61mV    126.2nV    2.83V
9.75ns    614.1mV    290.1nV    2.871V
11.35ns   2.124V     3.865uV    2.922V
13.7ns    2.491V     141.3mV    2.942V
16.15ns   2.541V     1.353V     2.947V
19.1ns    2.551V     1.75V      2.948V
58.4ns    2.552V     1.817V     2.948V
| Removed startup time: 0s 0s 0s  .
| Removed end time: 48.4ns.
[Falling Waveform]
R_fixture   = 50.0
V_fixture   = 0V
V_fixture_min = 0V
V_fixture_max = 0V
0s        2.552V     1.817V     2.948V
5.95ns    2.552V     1.817V     2.879V
7.9ns     2.552V     1.817V     18.07mV
10.9ns    2.526V     1.817V     2.191mV
11.65ns   2.084V     1.817V     1.556mV
12.75ns   205.3mV    1.817V     952.9uV
13.85ns   9.374mV    1.817V     596.9uV
15.8ns    3.386mV    1.586V     272.1uV
18.8ns    899uV      9.283mV    85.03uV
48.4ns    92.91nV    2.325uV    33.02nV
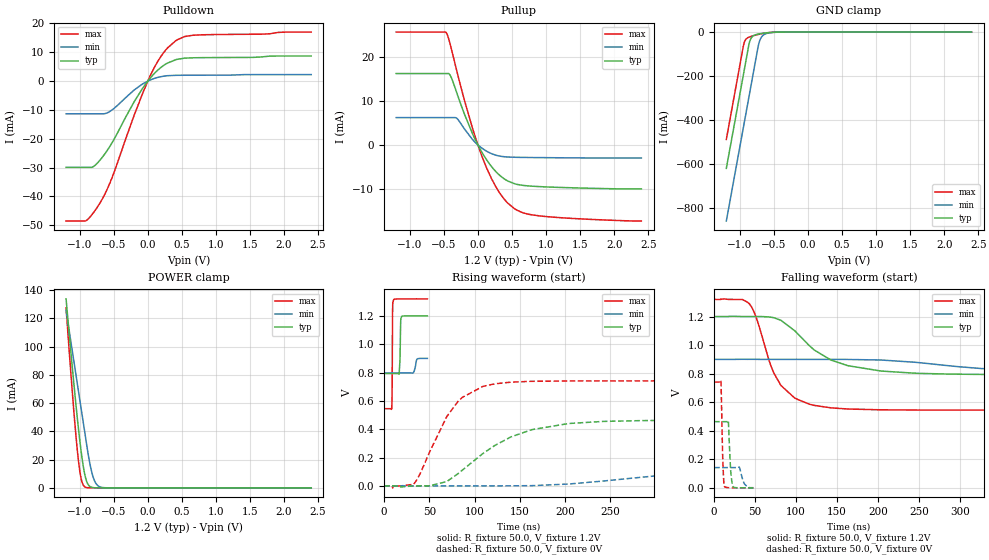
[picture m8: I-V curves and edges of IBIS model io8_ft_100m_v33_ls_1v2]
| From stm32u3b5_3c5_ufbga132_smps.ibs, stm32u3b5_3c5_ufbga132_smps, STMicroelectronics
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[Model]   io8_ft_100m_v33_ls_1v2
Model_type I/O
Polarity   Non-Inverting
Enable   Active-Low
| CAP_THRESHOLD on pad IOFT is "UDTCAPC" :
| Rising=30.0% of vddiom   Falling=70.0% of vddiom
| C_comp min and max val. don't necessarily correlate with the min and max pvt
| but are the smallest and greatest pad capacitance found.
| var   typ   min   max
C_comp   3.64340pF  3.44851pF  3.71561pF
|C_comp_pullup   2.21928pF  1.92711pF  2.35805pF
|C_comp_pulldown   1.42412pF  1.52140pF  1.35756pF
Vinl = 450.0mV
Vinh = 660.0mV
Vmeas = 600.0mV   | Reference voltage for timing measurements
Cref  = 50.0pF   | Timing specification test load capacitance value
Rref  = 1.0MOhm   | Timing specification test load resistance value
Vref  = 660.0mV   | Timing specification test load voltage
[Model Spec]
| TIME_THRESHOLD on pin ZIV33M is "CMOS" :
| Rising=50.0% of vddiom   Falling=50.0% of vddiom
Vinl 434.50000mV 327.50000mV 480.50000mV
Vinh 750.50000mV 549.50000mV 835.50000mV
| variable   typ   min   max
[Temperature Range] 25.0 130.0 -40.0
| variable   typ   min   max
[Voltage Range] 1.2V 900.0mV 1.32V
| variable   typ   min   max
[POWER Clamp Reference] 1.2V 900.0mV 1.32V
| variable   typ   min   max
[GND Clamp Reference] 0V 0V 0V
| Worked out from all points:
|   slope of the pulldown table from 0 to 0.18 V, typ, clamps not added: 40 ohm
|   slope of the pullup table from 0 to 0.18 V, typ, clamps not added: 40 ohm
|   GND clamp passes 1 mA (typ) near -0.50 V on its own axis
|   POWER clamp passes 1 mA (typ) near -0.85 V on its own axis
|   rising waveform, R_fixture 50.0, V_fixture 1.2V: 20-80 % time 755ps typ, 1.94ns min, 398ps max; typ from 0.793 V to 1.2 V
|   falling waveform, R_fixture 50.0, V_fixture 1.2V: 20-80 % time 59.3ns typ, 146ns min, 31.8ns max; typ from 1.2 V to 0.793 V
|   rising waveform, R_fixture 50.0, V_fixture 0V: 20-80 % time 68.5ns typ, 169ns min, 37.1ns max; typ from 0 V to 0.464 V
|   falling waveform, R_fixture 50.0, V_fixture 0V: 20-80 % time 2.51ns typ, 4.64ns min, 1.89ns max; typ from 0.464 V to 0 V
[POWER Clamp]
-1.2V     133.8mA    125.6mA    127.5mA
-1.08V    70.97mA    87.88mA    50.75mA
-1.04V    51.73mA    75.31mA    29.13mA
-1.01V    38.33mA    65.88mA    15.91mA
-970mV    22.56mA    53.3mA     4.74mA
-930mV    10.55mA    40.73mA    892.2uA
-890mV    3.611mA    28.15mA    138.3uA
-850mV    950.4uA    17.03mA    20.6uA
-810mV    222.1uA    8.794mA    3.05uA
-770mV    50.16uA    3.803mA    451.1nA
-650mV    561.7nA    165.6uA    1.537nA
2.4V      0A         0A         0A
[GND Clamp]
-1.2V     -620mA     -859.4mA   -488.5mA
-940mV    -178mA     -417.4mA   -50.52mA
-910mV    -127mA     -366.4mA   -31.92mA
-870mV    -59.03mA   -298.4mA   -23.56mA
-840mV    -30.06mA   -247.4mA   -20.12mA
-800mV    -16.5mA    -179.4mA   -16.42mA
-730mV    -9.175mA   -61.6mA    -10.9mA
-700mV    -7.461mA   -32.04mA   -8.862mA
-660mV    -5.584mA   -14.78mA   -6.456mA
-570mV    -2.482mA   -3.888mA   -2.491mA
-380mV    -62.94uA   -244.6uA   -21.21uA
2.4V      891.3pA    142.1nA    382.4pA
| variable   typ   min   max
[Pullup Reference] 1.2V 900.0mV 1.32V
| variable   typ   min   max
[Pulldown Reference] 0V 0V 0V
[Pullup]
-1.2V     16.16mA    6.187mA    25.56mA
-460mV    16.16mA    6.187mA    25.29mA
-400mV    15.55mA    6.187mA    22.33mA
-310mV    11.77mA    6.022mA    16.72mA
-80mV     2.558mA    1.232mA    3.812mA
80mV      -2.205mA   -948.4uA   -3.386mA
190mV     -4.701mA   -1.897mA   -7.304mA
310mV     -6.737mA   -2.489mA   -10.64mA
540mV     -8.791mA   -2.786mA   -14.47mA
740mV     -9.274mA   -2.836mA   -15.67mA
1.04V     -9.521mA   -2.882mA   -16.26mA
2.4V      -9.943mA   -2.948mA   -17.22mA
[Pulldown]
-1.2V     -29.93mA   -11.33mA   -48.55mA
-910mV    -29.93mA   -11.33mA   -48.48mA
-810mV    -29.8mA    -11.33mA   -46.03mA
-710mV    -27.65mA   -11.33mA   -42.6mA
-620mV    -24.89mA   -11.22mA   -38.69mA
-530mV    -21.58mA   -10.08mA   -33.79mA
-200mV    -7.157mA   -3.075mA   -11.82mA
40mV      1.18mA     424.7uA    2.081mA
230mV     5.395mA    1.701mA    9.799mA
420mV     7.512mA    2.016mA    14.19mA
670mV     8.097mA    2.046mA    15.93mA
2.4V      8.706mA    2.25mA     17.03mA
[Ramp]
dV/dt_r 278.13801mV/66.98994ns 85.17563mV/167.44001ns 444.65477mV/36.95187ns
dV/dt_f 244.21038mV/57.23203ns 61.561mV/143.4717ns 465.10826mV/30.87825ns
R_load = 50.0
| Removed startup time: 0s 0s 0s  .
| Removed end time: 47.95ns.
[Rising Waveform]
R_fixture   = 50.0
V_fixture   = 1.2V
V_fixture_min = 900.0mV
V_fixture_max = 1.32V
0s        793mV      797.4mV    544.8mV
8.55ns    793mV      797.4mV    543.3mV
9.05ns    793mV      797.4mV    704.1mV
9.6ns     793mV      797.4mV    1.258V
10.8ns    793mV      797.4mV    1.316V
16.75ns   788.3mV    797.4mV    1.319V
17.65ns   882.5mV    797.4mV    1.319V
18.55ns   1.167V     797.4mV    1.32V
19.6ns    1.197V     797.4mV    1.32V
47.95ns   1.2V       899.8mV    1.32V
| Removed startup time: 0s 0s 0s  .
| Removed end time: 1.99795us.
[Falling Waveform]
R_fixture   = 50.0
V_fixture   = 1.2V
V_fixture_min = 900.0mV
V_fixture_max = 1.32V
0s        1.2V       900mV      1.32V
43.75ns   1.2V       900.5mV    1.284V
52.15ns   1.2V       900.3mV    1.181V
72.95ns   1.192V     900mV      804.3mV
98.65ns   1.1V       900mV      627.9mV
122.4ns   965.4mV    900mV      577.6mV
163.1ns   856.1mV    899.4mV    552.4mV
254.2ns   801.4mV    874.8mV    545.1mV
530.1ns   793mV      803mV      544.8mV
1.998us   793mV      797.4mV    544.8mV
| Removed startup time: 0s 0s 0s  .
| Removed end time: 1.99795us.
[Rising Waveform]
R_fixture   = 50.0
V_fixture   = 0V
V_fixture_min = 0V
V_fixture_max = 0V
0s        4.987nV    173.7nV    3.506nV
33.5ns    -107uV     -898.6uV   17.42mV
69.35ns   30.4mV     -21.8uV    489.3mV
86.3ns    109.8mV    -12.76uV   623.8mV
109.1ns   227.8mV    47.99uV    701.7mV
140.2ns   345.7mV    351.9uV    732.1mV
203.9ns   440.1mV    12.97mV    740.5mV
299.1ns   461.5mV    69.93mV    741mV
570.9ns   463.5mV    137.3mV    741.1mV
1.998us   463.6mV    142mV      741.1mV
| Removed startup time: 0s 0s 0s  .
| Removed end time: 47.95ns.
[Falling Waveform]
R_fixture   = 50.0
V_fixture   = 0V
V_fixture_min = 0V
V_fixture_max = 0V
0s        463.6mV    142mV      741.1mV
8.35ns    463.6mV    142mV      750.1mV
10.65ns   463.6mV    142mV      191.9mV
12.75ns   463.6mV    142mV      8.669mV
17.35ns   470.5mV    142mV      1.647mV
20.3ns    117.6mV    142mV      797.6uV
22.55ns   13.73mV    142mV      500.2uV
30.65ns   558.4uV    145.9mV    216.4uV
37.2ns    208.7uV    27.16mV    239.2uV
47.95ns   109.3uV    1.283mV    179.4uV
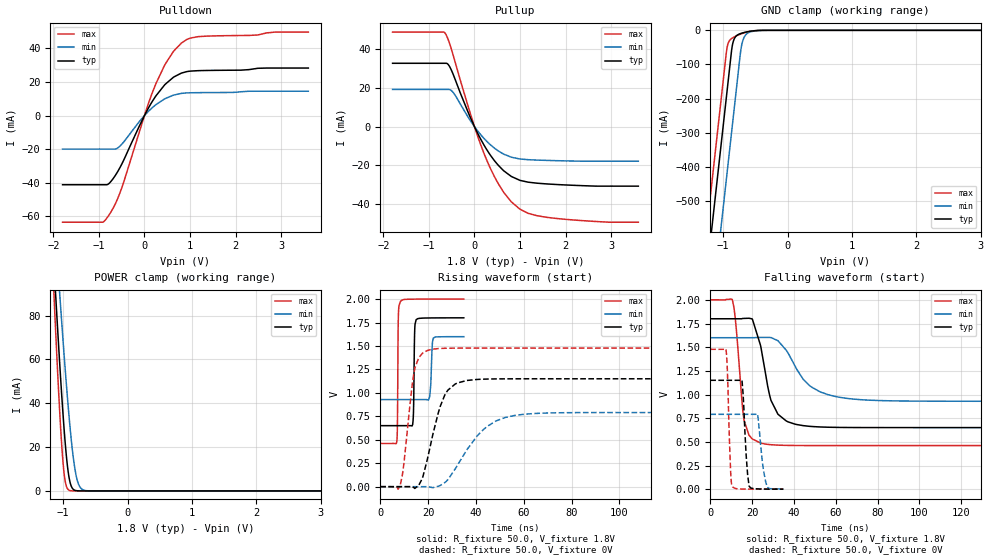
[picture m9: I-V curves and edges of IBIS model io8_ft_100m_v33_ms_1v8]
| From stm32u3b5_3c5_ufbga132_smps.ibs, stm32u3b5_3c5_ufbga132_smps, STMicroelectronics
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[Model]   io8_ft_100m_v33_ms_1v8
Model_type I/O
Polarity   Non-Inverting
Enable   Active-Low
| CAP_THRESHOLD on pad IOFT is "UDTCAPC" :
| Rising=30.0% of vddiom   Falling=70.0% of vddiom
| C_comp min and max val. don't necessarily correlate with the min and max pvt
| but are the smallest and greatest pad capacitance found.
| var   typ   min   max
C_comp   4.46110pF  4.37696pF  4.58318pF
|C_comp_pullup   2.75040pF  2.57422pF  2.90930pF
|C_comp_pulldown   1.71071pF  1.80275pF  1.67388pF
Vinl = 800.0mV
Vinh = 1.0V
Vmeas = 900.0mV   | Reference voltage for timing measurements
Cref  = 50.0pF   | Timing specification test load capacitance value
Rref  = 1.0MOhm   | Timing specification test load resistance value
Vref  = 990.0mV   | Timing specification test load voltage
[Model Spec]
| TIME_THRESHOLD on pin ZIV33M is "CMOS" :
| Rising=50.0% of vddiom   Falling=50.0% of vddiom
Vinl 689.50000mV 614.50000mV 772.50000mV
Vinh 1.08250V 955.50000mV 1.18750V
| variable   typ   min   max
[Temperature Range] 25.0 130.0 -40.0
| variable   typ   min   max
[Voltage Range] 1.8V 1.6V 2.0V
| variable   typ   min   max
[POWER Clamp Reference] 1.8V 1.6V 2.0V
| variable   typ   min   max
[GND Clamp Reference] 0V 0V 0V
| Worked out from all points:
|   slope of the pulldown table from 0 to 0.27 V, typ, clamps not added: 21.9 ohm
|   slope of the pullup table from 0 to 0.27 V, typ, clamps not added: 22.7 ohm
|   GND clamp passes 1 mA (typ) near -0.50 V on its own axis
|   POWER clamp passes 1 mA (typ) near -0.85 V on its own axis
|   rising waveform, R_fixture 50.0, V_fixture 1.8V: 20-80 % time 339ps typ, 621ps min, 268ps max; typ from 0.65 V to 1.8 V
|   falling waveform, R_fixture 50.0, V_fixture 1.8V: 20-80 % time 7.03ns typ, 13.3ns min, 3.46ns max; typ from 1.8 V to 0.65 V
|   rising waveform, R_fixture 50.0, V_fixture 0V: 20-80 % time 7.01ns typ, 13.7ns min, 3.8ns max; typ from 0 V to 1.15 V
|   falling waveform, R_fixture 50.0, V_fixture 0V: 20-80 % time 1.69ns typ, 2.37ns min, 1.26ns max; typ from 1.15 V to 0 V
[POWER Clamp]
-1.8V     478.8mA    439.5mA    561.1mA
-1.14V    101.7mA    127.5mA    87.74mA
-1.11V    86.11mA    114.3mA    68.77mA
-1.05V    56.42mA    88.49mA    34.19mA
-1.01V    38.33mA    71.95mA    15.91mA
-970mV    22.56mA    56.16mA    4.74mA
-910mV    6.426mA    34.56mA    354.8uA
-850mV    950.4uA    17.03mA    20.6uA
-800mV    153.4uA    7.248mA    1.891uA
-750mV    23.75uA    2.361mA    173.6nA
-670mV    1.188uA    286.7uA    3.927nA
3.6V      0A         0A         0A
[GND Clamp]
-1.8V     -1.641A    -1.882A    -1.509A
-1.24V    -689.3mA   -929.9mA   -557.3mA
-1.05V    -366.3mA   -606.9mA   -234.3mA
-950mV    -196.3mA   -436.9mA   -64.35mA
-930mV    -162.3mA   -402.9mA   -42.64mA
-870mV    -60.33mA   -300.9mA   -24.14mA
-850mV    -37.9mA    -266.9mA   -21.7mA
-770mV    -12.83mA   -130.9mA   -14.29mA
-730mV    -9.517mA   -63.9mA    -11.18mA
-690mV    -7.204mA   -27.69mA   -8.428mA
-530mV    -1.58mA    -2.534mA   -1.415mA
3.6V      1.308nA    187.1nA    582.2pA
| variable   typ   min   max
[Pullup Reference] 1.8V 1.6V 2.0V
| variable   typ   min   max
[Pulldown Reference] 0V 0V 0V
[Pullup]
-1.8V     32.84mA    19.29mA    49.01mA
-640mV    32.84mA    19.29mA    48.24mA
-570mV    31.97mA    19.29mA    44.61mA
-470mV    27.21mA    17.76mA    37.13mA
0V        662.6fA    158.4pA    3.85fA
280mV     -12.28mA   -7.824mA   -17.91mA
630mV     -22.57mA   -14.06mA   -33.59mA
810mV     -25.79mA   -15.81mA   -38.95mA
1V        -27.82mA   -16.74mA   -42.77mA
1.37V     -29.26mA   -17.3mA    -46.1mA
1.74V     -29.87mA   -17.57mA   -47.39mA
3.6V      -30.8mA    -17.88mA   -49.48mA
[Pulldown]
-1.8V     -41.16mA   -19.96mA   -63.43mA
-920mV    -41.16mA   -19.96mA   -63.43mA
-780mV    -40.43mA   -19.96mA   -59.18mA
-620mV    -34.74mA   -19.77mA   -51.3mA
-510mV    -29.46mA   -17.38mA   -43.8mA
0V        151.9fA    35.29pA    0A
250mV     11.64mA    6.428mA    18.87mA
460mV     18.67mA    10.12mA    30.76mA
630mV     22.61mA    12.05mA    37.86mA
810mV     25.21mA    13.14mA    43.03mA
1.18V     26.67mA    13.59mA    46.9mA
3.6V      28.21mA    14.43mA    49.6mA
[Ramp]
dV/dt_r 690.02408mV/6.84883ns 474.35977mV/13.61005ns 886.36697mV/3.7987ns
dV/dt_f 689.75464mV/6.39854ns 403.00329mV/13.11757ns 923.68053mV/3.44894ns
R_load = 50.0
| Removed startup time: 0s 0s 0s  .
| Removed end time: 34.95ns.
[Rising Waveform]
R_fixture   = 50.0
V_fixture   = 1.8V
V_fixture_min = 1.6V
V_fixture_max = 2.0V
0s        650.4mV    928.3mV    460.5mV
6.9ns     650.4mV    928.3mV    477.1mV
7.15ns    650.4mV    928.3mV    627.3mV
7.55ns    650.4mV    928.3mV    1.798V
8.55ns    650.4mV    928.3mV    1.979V
13.55ns   662.9mV    928.3mV    1.999V
15ns      1.78V      928.3mV    1.999V
20.7ns    1.799V     961.5mV    2V
22.15ns   1.799V     1.582V     2V
34.95ns   1.8V       1.599V     2V
| Removed startup time: 0s 0s 0s  .
| Removed end time: 197.95ns.
[Falling Waveform]
R_fixture   = 50.0
V_fixture   = 1.8V
V_fixture_min = 1.6V
V_fixture_max = 2.0V
0s        1.8V       1.6V       2V
10.55ns   1.8V       1.6V       2V
12.3ns    1.8V       1.6V       1.727V
16.15ns   1.804V     1.6V       728.8mV
20.05ns   1.798V     1.6V       531.9mV
24.05ns   1.518V     1.603V     487.4mV
29ns      939.3mV    1.602V     469.7mV
41.35ns   682.7mV    1.266V     461.3mV
68.7ns    651.1mV    950.9mV    460.5mV
197.9ns   650.4mV    928.3mV    460.5mV
| Removed startup time: 0s 0s 0s  .
| Removed end time: 197.9ns.
[Rising Waveform]
R_fixture   = 50.0
V_fixture   = 0V
V_fixture_min = 0V
V_fixture_max = 0V
0s        5.001nV    122.3nV    3.682nV
8.35ns    3.932nV    122.1nV    18.59mV
14.35ns   -17.53mV   116.9nV    1.248V
17.5ns    82.84mV    3.564uV    1.418V
20.2ns    349.7mV    -706.7uV   1.456V
27ns      977.9mV    43.56mV    1.475V
36.15ns   1.132V     389.8mV    1.477V
48.5ns    1.149V     701.9mV    1.477V
60.6ns    1.15V      773mV      1.477V
197.9ns   1.15V      790.6mV    1.477V
| Removed startup time: 0s 0s 0s  .
| Removed end time: 34.95ns.
[Falling Waveform]
R_fixture   = 50.0
V_fixture   = 0V
V_fixture_min = 0V
V_fixture_max = 0V
0s        1.15V      790.6mV    1.477V
7.5ns     1.15V      790.6mV    1.478V
8.15ns    1.15V      790.6mV    1.265V
9.75ns    1.15V      790.6mV    182.7mV
10.7ns    1.15V      790.6mV    23.59mV
15.15ns   1.149V     790.6mV    1.231mV
18.55ns   33.43mV    790.6mV    421.9uV
22.6ns    3.003mV    790.3mV    161.4uV
27.15ns   736.2uV    28.1mV     61.51uV
34.95ns   258.7uV    3.154mV    12.1uV
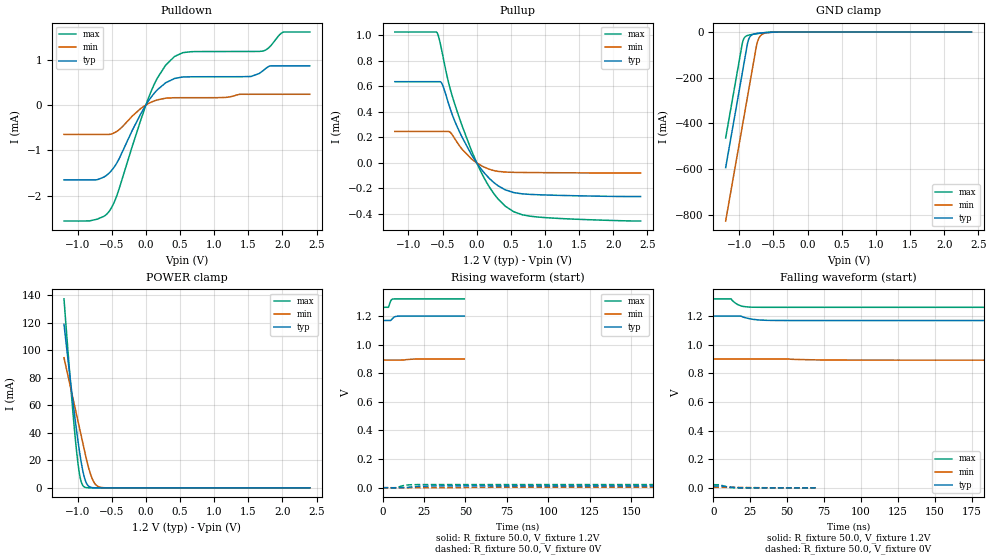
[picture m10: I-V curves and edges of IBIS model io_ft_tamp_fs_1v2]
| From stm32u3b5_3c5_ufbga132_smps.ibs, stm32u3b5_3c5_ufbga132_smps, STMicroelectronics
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[Model]   io_ft_tamp_fs_1v2
Model_type I/O
Polarity   Non-Inverting
Enable   Active-Low
| CAP_THRESHOLD on pad IOFT is "UDTCAPC" :
| Rising=30.0% of vddios   Falling=70.0% of vddios
| C_comp min and max val. don't necessarily correlate with the min and max pvt
| but are the smallest and greatest pad capacitance found.
| var   typ   min   max
C_comp   2.39258pF  2.36010pF  2.41953pF
|C_comp_pullup   1.38912pF  1.28771pF  1.47311pF
|C_comp_pulldown   1.00346pF  1.07239pF  946.42450fF
Vinl = 450.0mV
Vinh = 660.0mV
Vmeas = 600.0mV   | Reference voltage for timing measurements
Cref  = 50.0pF   | Timing specification test load capacitance value
Rref  = 1.0MOhm   | Timing specification test load resistance value
Vref  = 660.0mV   | Timing specification test load voltage
[Model Spec]
| TIME_THRESHOLD on pin ZIV11 is "CMOS" :
| Rising=50.0% of vdd   Falling=50.0% of vdd
Vinl 439.50000mV 331.50001mV 485.50000mV
Vinh 752.50000mV 552.50001mV 837.50000mV
| variable   typ   min   max
[Temperature Range] 25.0 130.0 -40.0
| variable   typ   min   max
[Voltage Range] 1.2V 900.0mV 1.32V
| variable   typ   min   max
[POWER Clamp Reference] 1.2V 900.0mV 1.32V
| variable   typ   min   max
[GND Clamp Reference] 0V 0V 0V
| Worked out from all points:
|   slope of the pulldown table from 0 to 0.18 V, typ, clamps not added: 514 ohm
|   slope of the pullup table from 0 to 0.18 V, typ, clamps not added: 1.52 kohm
|   GND clamp passes 1 mA (typ) near -0.53 V on its own axis
|   POWER clamp passes 1 mA (typ) near -0.83 V on its own axis
[POWER Clamp]
-1.2V     118.8mA    94.44mA    137.2mA
-1.09V    71.2mA     69.75mA    67.14mA
-1.02V    43.22mA    54.03mA    28.67mA
-990mV    32.26mA    47.3mA     15.78mA
-970mV    25.49mA    42.81mA    9.257mA
-940mV    16.45mA    36.08mA    3.257mA
-910mV    9.238mA    29.34mA    904.6uA
-860mV    2.387mA    18.53mA    87.46uA
-790mV    204.6uA    7.049mA    3.101uA
-730mV    21.91uA    2.041mA    176.4nA
-660mV    1.594uA    337.6uA    6.258nA
2.4V      0A         0A         0A
[GND Clamp]
-1.2V     -593.4mA   -826.9mA   -463.7mA
-960mV    -185.4mA   -418.9mA   -55.68mA
-940mV    -151.4mA   -384.9mA   -33.02mA
-880mV    -50.24mA   -282.9mA   -15.1mA
-850mV    -23.55mA   -231.9mA   -12.72mA
-810mV    -11.44mA   -163.9mA   -10.41mA
-740mV    -5.957mA   -49.45mA   -7.062mA
-710mV    -4.858mA   -24.97mA   -5.804mA
-670mV    -3.677mA   -10.87mA   -4.301mA
-590mV    -1.88mA    -3mA       -1.97mA
-390mV    -51.73uA   -182.4uA   -18.95uA
2.4V      708.1pA    117.2nA    245.1pA
| variable   typ   min   max
[Pullup Reference] 1.2V 900.0mV 1.32V
| variable   typ   min   max
[Pulldown Reference] 0V 0V 0V
[Pullup]
-1.2V     636.5uA    246.5uA    1.026mA
-580mV    636.5uA    246.5uA    1.02mA
-510mV    621.6uA    246.5uA    874.5uA
-430mV    494.4uA    246.5uA    668.1uA
-370mV    394.9uA    228.6uA    544.1uA
-240mV    229.7uA    125uA      329.8uA
-80mV     67.47uA    32.57uA    100.5uA
170mV     -113.3uA   -46.43uA   -175.6uA
420mV     -211.4uA   -71.81uA   -339.7uA
540mV     -232.4uA   -73.87uA   -382.1uA
790mV     -246.7uA   -75.44uA   -417.9uA
2.4V      -263.1uA   -78.22uA   -455.1uA
[Pulldown]
-1.2V     -1.647mA   -647.6uA   -2.554mA
-730mV    -1.647mA   -647.6uA   -2.52mA
-530mV    -1.485mA   -646.4uA   -2.323mA
-420mV    -1.261mA   -574.4uA   -1.968mA
80mV      177.8uA    62.75uA    313.5uA
290mV     489.8uA    149.4uA    878.6uA
420mV     583.8uA    159.4uA    1.068mA
670mV     620.6uA    160.1uA    1.174mA
1.54V     627.5uA    235.3uA    1.178mA
1.71V     748.6uA    235.3uA    1.186mA
2.01V     861.3uA    235.3uA    1.602mA
2.4V      861.3uA    235.3uA    1.605mA
[Ramp]
dV/dt_r 7.61977mV/7.87431ns 2.27601mV/20.96053ns 13.1252mV/4.50512ns
dV/dt_f 18.65976mV/8.54388ns 4.80671mV/20.82541ns 35.31842mV/5.31138ns
R_load = 50.0
| Removed startup time: 0s 0s 0s  .
| Removed end time: 49.25ns.
[Rising Waveform]
R_fixture   = 50.0
V_fixture   = 1.2V
V_fixture_min = 900.0mV
V_fixture_max = 1.32V
0s        1.169V     892mV      1.261V
3.5ns     1.169V     892mV      1.261V
3.75ns    1.169V     892mV      1.266V
5.05ns    1.171V     892mV      1.308V
5.75ns    1.179V     892mV      1.317V
6.55ns    1.189V     892mV      1.319V
8.05ns    1.197V     892mV      1.319V
10.05ns   1.2V       892mV      1.32V
21.15ns   1.2V       899.4mV    1.32V
49.25ns   1.2V       900mV      1.32V
| Removed startup time: 0s 0s 0s  .
| Removed end time: 249.25ns.
[Falling Waveform]
R_fixture   = 50.0
V_fixture   = 1.2V
V_fixture_min = 900.0mV
V_fixture_max = 1.32V
0s        1.2V       900mV      1.32V
11.95ns   1.2V       900mV      1.32V
15.25ns   1.2V       900mV      1.288V
18.7ns    1.2V       900mV      1.271V
20.35ns   1.192V     900mV      1.267V
27.2ns    1.177V     900mV      1.262V
35.6ns    1.17V      900mV      1.261V
45.8ns    1.169V     900mV      1.261V
86.5ns    1.169V     892.6mV    1.261V
249.3ns   1.169V     892mV      1.261V
| Removed startup time: 0s 0s 0s  .
| Removed end time: 499.25ns.
[Rising Waveform]
R_fixture   = 50.0
V_fixture   = 0V
V_fixture_min = 0V
V_fixture_max = 0V
0s        10.41nV    204nV      9.892nV
7.95ns    -403.1uV   1.498uV    -140.1uV
11.65ns   -66.94uV   -34.83uV   12.2mV
13.9ns    1.238mV    -101.3uV   17.52mV
17.25ns   5.16mV     -100.7uV   20.77mV
21.75ns   9.405mV    -109.3uV   21.69mV
30.55ns   12.26mV    -14.78uV   21.86mV
61.15ns   12.69mV    2.865mV    21.87mV
91.7ns    12.69mV    3.72mV     21.87mV
499.3ns   12.7mV     3.794mV    21.88mV
| Removed startup time: 0s 0s 0s  .
| Removed end time: 69.25ns.
[Falling Waveform]
R_fixture   = 50.0
V_fixture   = 0V
V_fixture_min = 0V
V_fixture_max = 0V
0s        12.7mV     3.795mV    21.88mV
4.2ns     12.69mV    3.796mV    21.85mV
5.45ns    12.61mV    3.795mV    17.73mV
9.85ns    7.169mV    3.793mV    5.317mV
12.05ns   4.897mV    3.802mV    1.687mV
14.6ns    2.735mV    3.536mV    409.2uV
18.4ns    757.2uV    2.902mV    147.8uV
22.65ns   187.7uV    2.256mV    63.95uV
41ns      16.96uV    367.7uV    1.085uV
69.25ns   384.5nV    27.76uV    12.22nV
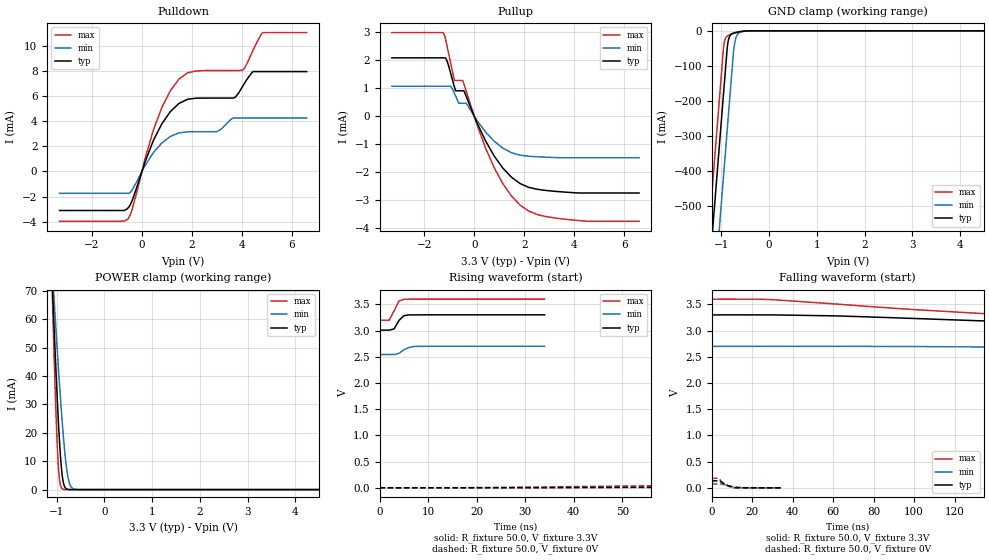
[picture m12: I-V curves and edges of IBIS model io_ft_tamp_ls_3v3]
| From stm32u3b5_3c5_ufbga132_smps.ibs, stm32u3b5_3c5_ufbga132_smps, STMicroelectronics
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[Model]   io_ft_tamp_ls_3v3
Model_type I/O
Polarity   Non-Inverting
Enable   Active-Low
| CAP_THRESHOLD on pad IOFT is "UDTCAPC" :
| Rising=30.0% of vddios   Falling=70.0% of vddios
| C_comp min and max val. don't necessarily correlate with the min and max pvt
| but are the smallest and greatest pad capacitance found.
| var   typ   min   max
C_comp   2.95022pF  2.93317pF  3.00716pF
|C_comp_pullup   1.82449pF  1.69913pF  1.79117pF
|C_comp_pulldown   1.12573pF  1.23404pF  1.21599pF
Vinl = 1.35V
Vinh = 1.8V
Vmeas = 1.65V   | Reference voltage for timing measurements
Cref  = 50.0pF   | Timing specification test load capacitance value
Rref  = 1.0MOhm   | Timing specification test load resistance value
Vref  = 1.815V   | Timing specification test load voltage
[Model Spec]
| TIME_THRESHOLD on pin ZIV11 is "CMOS" :
| Rising=50.0% of vdd   Falling=50.0% of vdd
Vinl 1.27950V 1.06950V 1.36550V
Vinh 1.78950V 1.51350V 1.89450V
| variable   typ   min   max
[Temperature Range] 25.0 130.0 -40.0
| variable   typ   min   max
[Voltage Range] 3.3V 2.7V 3.6V
| variable   typ   min   max
[POWER Clamp Reference] 3.3V 2.7V 3.6V
| variable   typ   min   max
[GND Clamp Reference] 0V 0V 0V
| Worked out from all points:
|   slope of the pulldown table from 0 to 0.495 V, typ, clamps not added: 190 ohm
|   slope of the pullup table from 0 to 0.495 V, typ, clamps not added: 524 ohm
|   GND clamp passes 1 mA (typ) near -0.53 V on its own axis
|   POWER clamp passes 1 mA (typ) near -0.83 V on its own axis
|   rising waveform, R_fixture 50.0, V_fixture 3.3V: 20-80 % time 1.32ns typ, 1.68ns min, 1.31ns max; typ from 3.01 V to 3.3 V
|   falling waveform, R_fixture 50.0, V_fixture 3.3V: 20-80 % time 142ns typ, 244ns min, 100ns max; typ from 3.3 V to 3.01 V
|   rising waveform, R_fixture 50.0, V_fixture 0V: 20-80 % time 167ns typ, 297ns min, 117ns max; typ from 0 V to 0.134 V
|   falling waveform, R_fixture 50.0, V_fixture 0V: 20-80 % time 4.46ns typ, 6.35ns min, 3.76ns max; typ from 0.134 V to 0 V
[POWER Clamp]
-3.3V     1.126A     769.5mA    1.647A
-1.1V     75.38mA    79.63mA    73.18mA
-1.09V    71.2mA     76.8mA     67.14mA
-1.08V    67.05mA    73.98mA    61.2mA
-1.06V    58.89mA    68.38mA    49.67mA
-1.01V    39.47mA    54.71mA    24.03mA
-970mV    25.49mA    44.18mA    9.257mA
-930mV    13.81mA    34.16mA    2.168mA
-870mV    3.251mA    20.56mA    140.6uA
-760mV    67.19uA    3.98mA     739.7nA
-630mV    518.2nA    149.1uA    1.746nA
6.6V      0A         0A         0A
[GND Clamp]
-3.3V     -4.165A    -4.4A      -4.034A
-1.25V    -679.9mA   -915.1mA   -549mA
-960mV    -186.9mA   -422.1mA   -55.97mA
-950mV    -169.9mA   -405.1mA   -42.45mA
-920mV    -118.9mA   -354.1mA   -22.92mA
-880mV    -51.66mA   -286.1mA   -15.35mA
-860mV    -30.97mA   -252.1mA   -13.65mA
-760mV    -7.32mA    -82.07mA   -8.144mA
-730mV    -5.898mA   -41.75mA   -6.789mA
-680mV    -4.176mA   -14.72mA   -4.769mA
-480mV    -457.9uA   -835.7uA   -334.7uA
6.6V      1.896nA    294.7nA    697.8pA
| variable   typ   min   max
[Pullup Reference] 3.3V 2.7V 3.6V
| variable   typ   min   max
[Pulldown Reference] 0V 0V 0V
[Pullup]
-3.3V     2.089mA    1.077mA    2.991mA
-1.24V    2.089mA    1.077mA    2.984mA
-1.09V    1.972mA    1.077mA    2.509mA
-800mV    1.069mA    833.6uA    1.292mA
-620mV    912.8uA    470.5uA    1.283mA
-460mV    912.8uA    470.5uA    1.272mA
-310mV    685uA      450.1uA    859.8uA
120mV     -252.2uA   -163.5uA   -324.6uA
800mV     -1.419mA   -890.8uA   -1.837mA
1.83V     -2.397mA   -1.386mA   -3.165mA
3.3V      -2.682mA   -1.473mA   -3.636mA
6.6V      -2.736mA   -1.477mA   -3.747mA
[Pulldown]
-3.3V     -3.112mA   -1.746mA   -3.972mA
-560mV    -2.917mA   -1.746mA   -3.78mA
-390mV    -2.313mA   -1.474mA   -2.998mA
460mV     2.475mA    1.504mA    3.307mA
800mV     3.8mA      2.27mA     5.099mA
1.48V     5.408mA    3.066mA    7.346mA
3.01V     5.836mA    3.17mA     8.031mA
3.67V     5.851mA    4.245mA    8.031mA
4.03V     6.763mA    4.245mA    8.067mA
4.43V     7.913mA    4.245mA    9.564mA
4.84V     7.947mA    4.245mA    11.05mA
6.6V      7.947mA    4.245mA    11.05mA
[Ramp]
dV/dt_r 80.14348mV/165.82257ns 43.41859mV/295.82784ns 109.51449mV/115.87804ns
dV/dt_f 175.11847mV/142.37618ns 94.56507mV/243.00547ns 240.98461mV/99.95525ns
R_load = 50.0
| Removed startup time: 0s 0s 0s  .
| Removed end time: 34.0ns.
[Rising Waveform]
R_fixture   = 50.0
V_fixture   = 3.3V
V_fixture_min = 2.7V
V_fixture_max = 3.6V
0s        3.008V     2.542V     3.198V
2ns       3.008V     2.542V     3.198V
3ns       3.032V     2.542V     3.376V
4ns       3.193V     2.563V     3.564V
5ns       3.283V     2.634V     3.598V
6ns       3.299V     2.675V     3.599V
7ns       3.299V     2.695V     3.6V
8ns       3.3V       2.699V     3.6V
34ns      3.3V       2.7V       3.6V
| Removed startup time: 0s 0s 0s  .
| Removed end time: 1.49925us.
[Falling Waveform]
R_fixture   = 50.0
V_fixture   = 3.3V
V_fixture_min = 2.7V
V_fixture_max = 3.6V
0s        3.3V       2.7V       3.6V
30.6ns    3.3V       2.7V       3.59V
61.2ns    3.281V     2.7V       3.508V
103ns     3.228V     2.696V     3.394V
158.5ns   3.154V     2.681V     3.277V
183.6ns   3.122V     2.672V     3.246V
244.8ns   3.059V     2.648V     3.212V
367.2ns   3.017V     2.595V     3.199V
581.4ns   3.009V     2.552V     3.198V
1.499us   3.008V     2.542V     3.198V
| Removed startup time: 0s 0s 0s  .
| Removed end time: 1.4992us.
[Rising Waveform]
R_fixture   = 50.0
V_fixture   = 0V
V_fixture_min = 0V
V_fixture_max = 0V
0s        42.36nV    238.8nV    101.2nV
20.3ns    4.751uV    -23.01uV   2.369mV
61.2ns    13.96mV    598.5uV    43.43mV
96.5ns    32.03mV    3.716mV    81.38mV
161.3ns   65.89mV    12.56mV    139.9mV
214.2ns   92.99mV    20.62mV    164.7mV
275.4ns   113mV      30.52mV    176.2mV
397.8ns   128.6mV    50.08mV    181.7mV
642.5ns   133.3mV    67.51mV    182.5mV
1.499us   133.6mV    72.36mV    182.5mV
| Removed startup time: 0s 0s 0s  .
| Removed end time: 34.25ns.
[Falling Waveform]
R_fixture   = 50.0
V_fixture   = 0V
V_fixture_min = 0V
V_fixture_max = 0V
0s        133.6mV    72.4mV     182.5mV
3.2ns     133.6mV    72.4mV     182.1mV
3.85ns    131.4mV    72.39mV    159mV
5.15ns    98.01mV    69.52mV    105.8mV
6.8ns     60.73mV    52.99mV    61.24mV
8.6ns     34.67mV    36.34mV    24.46mV
10.4ns    15.62mV    24.85mV    2.675mV
12.6ns    1.629mV    14.69mV    386.8uV
17.5ns    134uV      1.204mV    60.78uV
34.25ns   14.92uV    13.58uV    26.75uV
